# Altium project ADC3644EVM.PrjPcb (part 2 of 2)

## Sheet ADC Inputs.SchDoc: ADC Inputs
size 431 x 279 mm; Date: Not shown in title block; ApprovedBy: Not shown in title block; CheckedBy: Not shown in title block; Author: Not shown in title block; CompanyName: Not shown in title block; Engineer: Not shown in title block; Organization: Not shown in title block; Address1: Not shown in title block; Address2: Not shown in title block; Address3: Not shown in title block; Address4: Not shown in title block; DocumentNumber: 1; Revision: Use project parameter SCH_Rev; SheetNumber: 9; SheetTotal: 15; PageSetup: Record=PageOptions¦CenterHorizontal=True¦CenterVertical=True¦PrintScale=1.00¦XCorrection=1.00¦YCorrection=1.00¦PrintKind=0¦BorderSize=5000000¦LeftOffset=0¦BottomOffset=0¦Orientation=2¦PaperLength=1000¦PaperWidth=1000¦Scale=100¦PaperSource=15¦PrintQuality=600¦MediaType=1¦DitherType=10¦PaperKind=Letter¦PrintScaleMode=1

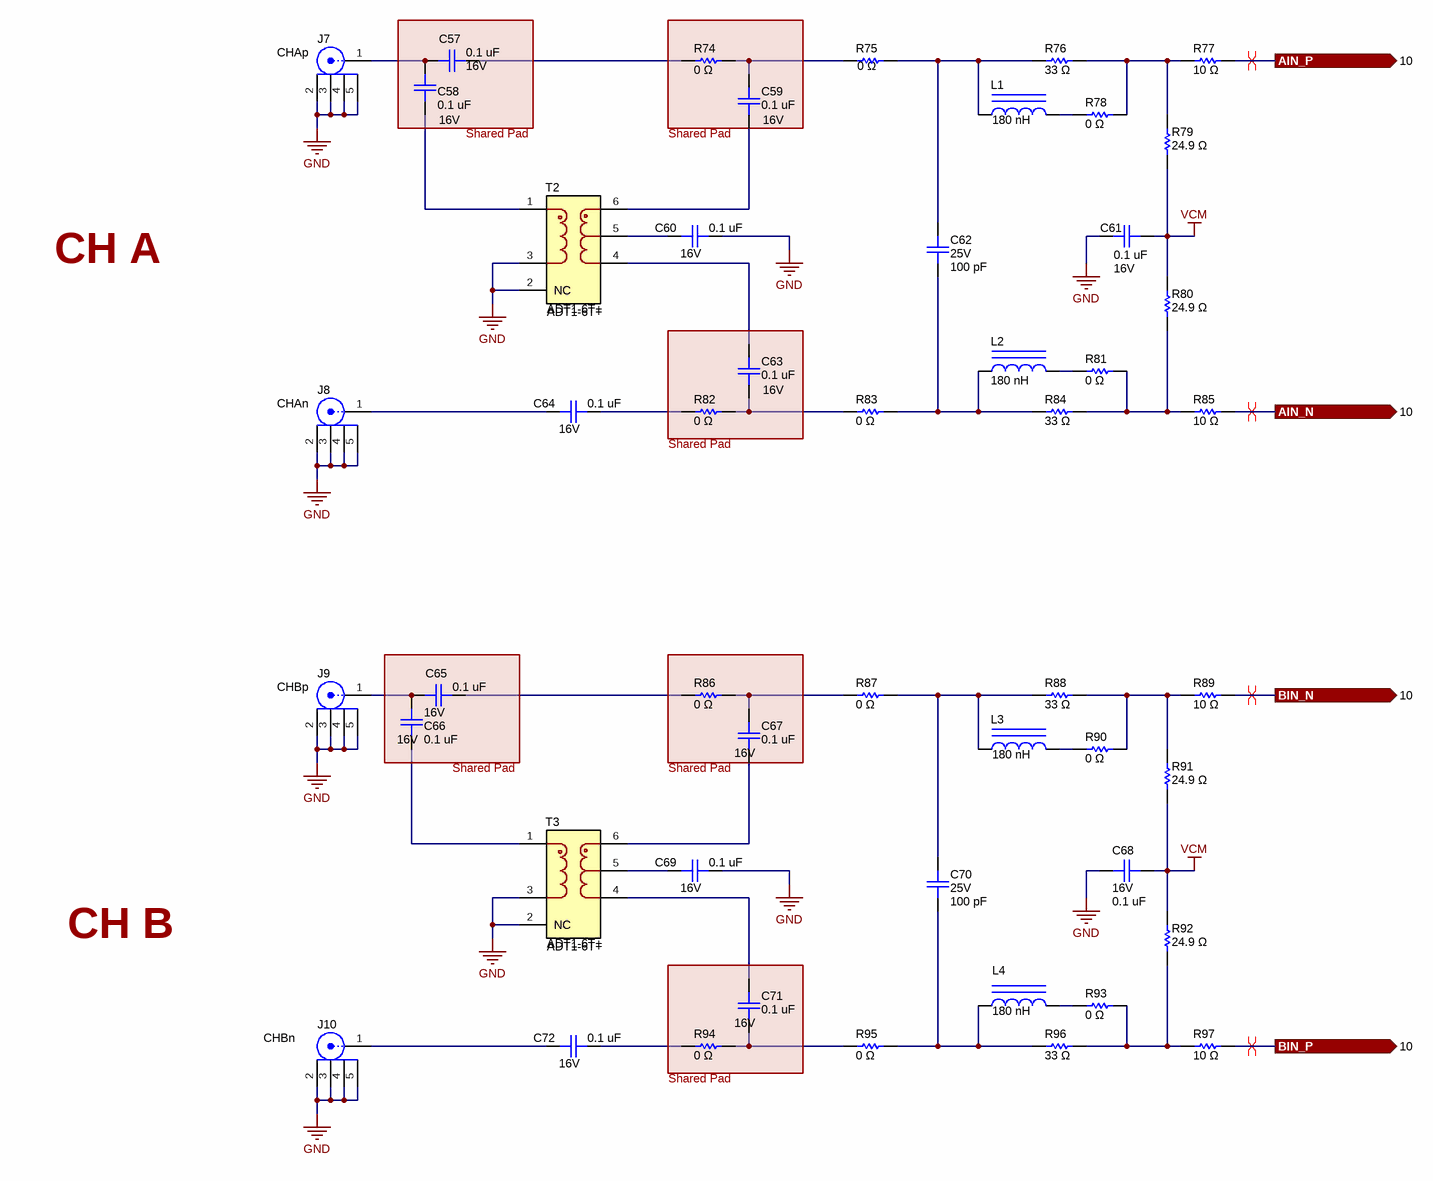
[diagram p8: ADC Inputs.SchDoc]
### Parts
(Parts that share a designator on the sheet are numbered #1, #2 ... from top to bottom, then left to right.)
?#4  Shared Pad  (graphical)
?#5  Shared Pad  (graphical)
?#6  Shared Pad  (graphical)
?#7  Shared Pad  (graphical)
?#8  Shared Pad  (graphical)
?#9  Shared Pad  (graphical)
C57  value 0.1 uF  Voltage - Rated: 16V  [0201_cap]  (hidden comment: GRM033Z71C104ME14D)
C58  value 0.1 uF  Voltage - Rated: 16V  [0201_cap]  (hidden comment: GRM033Z71C104ME14D)
C59  value 0.1 uF  Voltage - Rated: 16V  [0201_cap]  (hidden comment: GRM033Z71C104ME14D)
C60  value 0.1 uF  Voltage - Rated: 16V  [0201_cap]  (hidden comment: GRM033Z71C104ME14D)
C61  value 0.1 uF  Voltage - Rated: 16V  [0201_cap]  (hidden comment: GRM033Z71C104ME14D)
C62  value 100 pF  Voltage - Rated: 25V  [0201_cap]  (hidden comment: CGA1A2X7R1E101M030BA)
C63  value 0.1 uF  Voltage - Rated: 16V  [0201_cap]  (hidden comment: GRM033Z71C104ME14D)
C64  value 0.1 uF  Voltage - Rated: 16V  [0201_cap]  (hidden comment: GRM033Z71C104ME14D)
C65  value 0.1 uF  Voltage - Rated: 16V  [0201_cap]  (hidden comment: GRM033Z71C104ME14D)
C66  value 0.1 uF  Voltage - Rated: 16V  [0201_cap]  (hidden comment: GRM033Z71C104ME14D)
C67  value 0.1 uF  Voltage - Rated: 16V  [0201_cap]  (hidden comment: GRM033Z71C104ME14D)
C68  value 0.1 uF  Voltage - Rated: 16V  [0201_cap]  (hidden comment: GRM033Z71C104ME14D)
C69  value 0.1 uF  Voltage - Rated: 16V  [0201_cap]  (hidden comment: GRM033Z71C104ME14D)
C70  value 100 pF  Voltage - Rated: 25V  [0201_cap]  (hidden comment: CGA1A2X7R1E101M030BA)
C71  value 0.1 uF  Voltage - Rated: 16V  [0201_cap]  (hidden comment: GRM033Z71C104ME14D)
C72  value 0.1 uF  Voltage - Rated: 16V  [0201_cap]  (hidden comment: GRM033Z71C104ME14D)
J7  Text1: CHAp  [FP-132134-15_CONN_SMA_JACK-MFG]  (hidden comment: 132134-15)
J8  Text1: CHAn  [FP-132134-15_CONN_SMA_JACK-MFG]  (hidden comment: 132134-15)
J9  Text1: CHBp  [FP-132134-15_CONN_SMA_JACK-MFG]  (hidden comment: 132134-15)
J10  Text1: CHBn  [FP-132134-15_CONN_SMA_JACK-MFG]  (hidden comment: 132134-15)
L1  180 nH  [IND_LQG15H]
L2  180 nH  [IND_LQG15H]
L3  180 nH  [IND_LQG15H]
L4  180 nH  [IND_LQG15H]
R74  value 0 Ω  [0201]  (hidden comment: ERJ-1GN0R00C)
R75  value 0 Ω  [0201]  (hidden comment: ERJ-1GN0R00C)
R76  value 33 Ω  [0201]  (hidden comment: ERJ-1GNF33R0C)
R77  value 10 Ω  [0201]  (hidden comment: ERJ-1GNF10R0C)
R78  value 0 Ω  [0201]  (hidden comment: ERJ-1GN0R00C)
R79  value 24.9 Ω  [0201]  (hidden comment: ERJ-1GNF24R9C)
R80  value 24.9 Ω  [0201]  (hidden comment: ERJ-1GNF24R9C)
R81  value 0 Ω  [0201]  (hidden comment: ERJ-1GN0R00C)
R82  value 0 Ω  [0201]  (hidden comment: ERJ-1GN0R00C)
R83  value 0 Ω  [0201]  (hidden comment: ERJ-1GN0R00C)
R84  value 33 Ω  [0201]  (hidden comment: ERJ-1GNF33R0C)
R85  value 10 Ω  [0201]  (hidden comment: ERJ-1GNF10R0C)
R86  value 0 Ω  [0201]  (hidden comment: ERJ-1GN0R00C)
R87  value 0 Ω  [0201]  (hidden comment: ERJ-1GN0R00C)
R88  value 33 Ω  [0201]  (hidden comment: ERJ-1GNF33R0C)
R89  value 10 Ω  [0201]  (hidden comment: ERJ-1GNF10R0C)
R90  value 0 Ω  [0201]  (hidden comment: ERJ-1GN0R00C)
R91  value 24.9 Ω  [0201]  (hidden comment: ERJ-1GNF24R9C)
R92  value 24.9 Ω  [0201]  (hidden comment: ERJ-1GNF24R9C)
R93  value 0 Ω  [0201]  (hidden comment: ERJ-1GN0R00C)
R94  value 0 Ω  [0201]  (hidden comment: ERJ-1GN0R00C)
R95  value 0 Ω  [0201]  (hidden comment: ERJ-1GN0R00C)
R96  value 33 Ω  [0201]  (hidden comment: ERJ-1GNF33R0C)
R97  value 10 Ω  [0201]  (hidden comment: ERJ-1GNF10R0C)
T2  ADT1-6T+  [CD637]
T3  ADT1-6T+  [CD637]

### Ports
AIN_N (out, see 10), AIN_P (out, see 10), BIN_N (out, see 10), BIN_P (out, see 10)

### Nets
GND: C60.2 C61.1 C68.1 C69.2 J7.2 J7.3 J7.4 J7.5 J8.2 J8.3 J8.4 J8.5 J9.2 J9.3 J9.4 J9.5 J10.2 J10.3 J10.4 J10.5 T2.2(NC) T2.3 T3.2(NC) T3.3
VCM: C61.2 C68.2 R79.1 R80.2 R91.1 R92.2
AIN_N: R85.2 ; port AIN_N
AIN_P: R77.2 ; port AIN_P
BIN_N: R89.2 ; port BIN_N
BIN_P: R97.2 ; port BIN_P
NetC57_1: C57.1 C58.1 J7.1
NetC57_2: C57.2 R74.1
NetC58_2: C58.2 T2.1
NetC59_1: C59.1 T2.6
NetC59_2: C59.2 R74.2 R75.1
NetC60_1: C60.1 T2.5
NetC62_1: C62.1 L2.1 R83.2 R84.1
NetC62_2: C62.2 L1.1 R75.2 R76.1
NetC63_1: C63.1 R82.2 R83.1
NetC63_2: C63.2 T2.4
NetC64_1: C64.1 J8.1
NetC64_2: C64.2 R82.1
NetC65_1: C65.1 C66.1 J9.1
NetC65_2: C65.2 R86.1
NetC66_2: C66.2 T3.1
NetC67_1: C67.1 T3.6
NetC67_2: C67.2 R86.2 R87.1
NetC69_1: C69.1 T3.5
NetC70_1: C70.1 L4.1 R95.2 R96.1
NetC70_2: C70.2 L3.1 R87.2 R88.1
NetC71_1: C71.1 R94.2 R95.1
NetC71_2: C71.2 T3.4
NetC72_1: C72.1 J10.1
NetC72_2: C72.2 R94.1
NetL1_2: L1.2 R78.1
NetL2_2: L2.2 R81.1
NetL3_2: L3.2 R90.1
NetL4_2: L4.2 R93.1
NetR76_2: R76.2 R77.1 R78.2 R79.2
NetR80_1: R80.1 R81.2 R84.2 R85.1
NetR88_2: R88.2 R89.1 R90.2 R91.2
NetR92_1: R92.1 R93.2 R96.2 R97.1

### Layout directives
differential pair: AIN_N, AIN_P, BIN_N, BIN_P

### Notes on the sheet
- CH A
- CH B

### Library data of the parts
?#4-?#9 = Swizzle: Schematic notation to show that the pads of two components should be overlapped
C57-C61 C63-C69 C71 C72 = capcc09270: CAP CER 0.1UF 16V X7R 0201; Manufacturer: Murata Electronics; CompType: Capacitor Ceramic; Tolerance: ±20%; SizeX_mm: 0.6; SizeY_mm: 0.3; SizeZ_mm: 0.33
C62 C70 = capcc06388: CAP CER 100PF 25V X7R 0201; Manufacturer: TDK Corporation; CompType: Capacitor Ceramic; Tolerance: ±20%; SizeX_mm: 0.6; SizeY_mm: 0.3; SizeZ_mm: 0.33
J7-J10 = 132134-15: SMA Connector Jack, Female Socket 50Ohm Surface Mount, Through Hole Solder; Manufacturer: Amphenol RF; UniqueID: cmp00028; CompType: RF Connector
L1-L4 = LQG15HSR18J02D: Inductor, Multilayer, Air Core, 180 nH, 0.14 A, 3.38 ohm, SMD; Manufacturer: MuRata; Isat: 0.14A @ % inductance drop; Irms: 0.14A @ C rise; Green_Lifecycle: Active; SizeAreaWB_mm2: 3; DCR_ohm: 3.38; Green_REACh: Passed; Value: 180nH; Imax_A: 140mA; SizeZ_mm: 0.55; SizeX_mm: 1; SizeY_mm: 0.5; Value2: 0.14A; AEC Category: Q200
R74 R75 R78 R81-R83 R86 R87 R90 R93-R95 = RSMD020101699: RES SMD 0 OHM JUMPER 1/20W 0201; Manufacturer: Panasonic Electronic Components; CompType: Resistor SMD; Power (Watts): 0.05W, 1/20W
R76 R84 R88 R96 = RSMD020100013: RES SMD 33 OHM 1% 1/20W 0201; Manufacturer: Panasonic Electronic Components; CompType: Resistor SMD; Power (Watts): 0.05W, 1/20W; Temperature Coefficient: ±200ppm/°C
R77 R85 R89 R97 = RSMD020100179: RES SMD 10 OHM 1% 1/20W 0201; Manufacturer: Panasonic Electronic Components; CompType: Resistor SMD; Power (Watts): 0.05W, 1/20W; Temperature Coefficient: ±200ppm/°C
R79 R80 R91 R92 = RSMD020100010: RES SMD 24.9 OHM 1% 1/20W 0201; Manufacturer: Panasonic Electronic Components; CompType: Resistor SMD; Power (Watts): 0.05W, 1/20W; Temperature Coefficient: ±200ppm/°C
T2 T3 = ADT1-6T+: Transformer 50Ω/0.03 to 125 MHz; Manufacturer: Mini-Circuits; Rsec1_ohm: 50; Symbol Name: SYM-ADT1-6T+; Ns1toNp: 1:1; SizeZ_mm: .206inch; AEC Qualified: No

## Sheet DUT IO.SchDoc: ADC IO
size 431 x 279 mm; Date: Not shown in title block; ApprovedBy: Not shown in title block; CheckedBy: Not shown in title block; Author: Not shown in title block; CompanyName: Not shown in title block; Engineer: Not shown in title block; Organization: Not shown in title block; Address1: Not shown in title block; Address2: Not shown in title block; Address3: Not shown in title block; Address4: Not shown in title block; DocumentNumber: 1; Revision: Use project parameter SCH_Rev; SheetNumber: 10; SheetTotal: 15; PageSetup: Record=PageOptions¦CenterHorizontal=True¦CenterVertical=True¦PrintScale=1.00¦XCorrection=1.00¦YCorrection=1.00¦PrintKind=0¦BorderSize=5000000¦LeftOffset=0¦BottomOffset=0¦Orientation=2¦PaperLength=1000¦PaperWidth=1000¦Scale=100¦PaperSource=15¦PrintQuality=600¦MediaType=1¦DitherType=10¦PaperKind=Letter¦PrintScaleMode=1

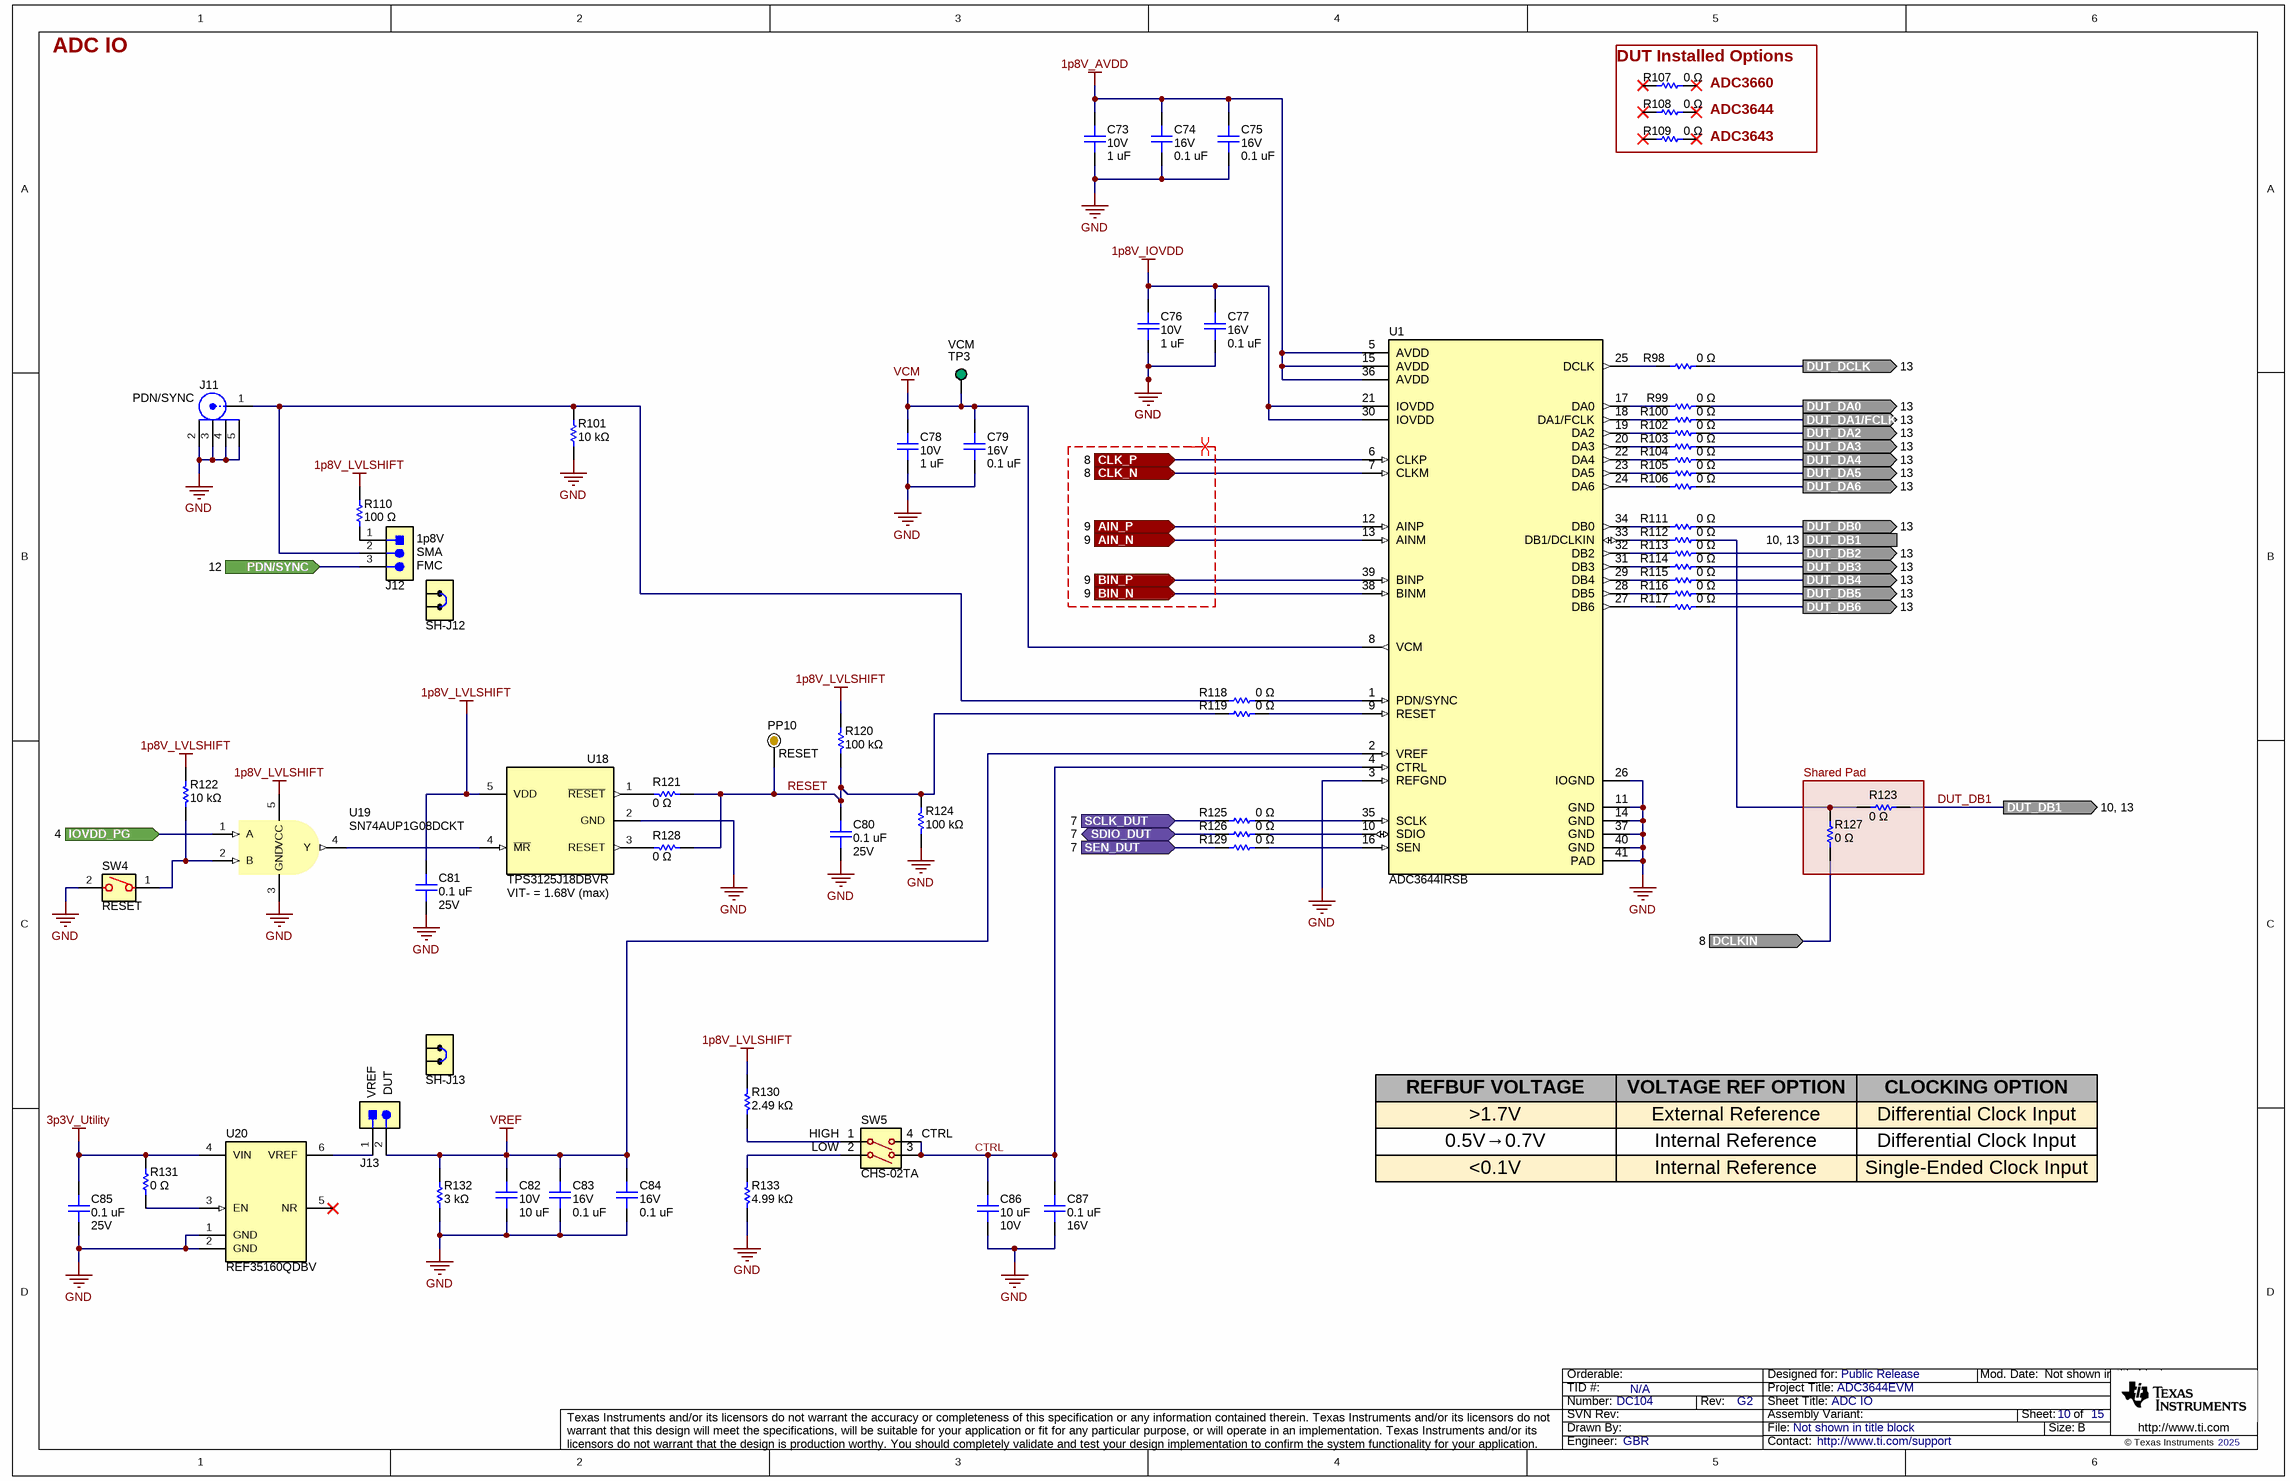
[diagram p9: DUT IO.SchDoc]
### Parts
(Parts that share a designator on the sheet are numbered #1, #2 ... from top to bottom, then left to right.)
?#10  Shared Pad  (graphical)
C73  value 1 uF  Voltage - Rated: 10V  [0201_cap]  (hidden comment: GRM033R61A105ME44D)
C74  value 0.1 uF  Voltage - Rated: 16V  [0201_cap]  (hidden comment: GRM033Z71C104ME14D)
C75  value 0.1 uF  Voltage - Rated: 16V  [0201_cap]  (hidden comment: GRM033Z71C104ME14D)
C76  value 1 uF  Voltage - Rated: 10V  [0201_cap]  (hidden comment: GRM033R61A105ME44D)
C77  value 0.1 uF  Voltage - Rated: 16V  [0201_cap]  (hidden comment: GRM033Z71C104ME14D)
C78  value 1 uF  Voltage - Rated: 10V  [0201_cap]  (hidden comment: GRM033R61A105ME44D)
C79  value 0.1 uF  Voltage - Rated: 16V  [0201_cap]  (hidden comment: GRM033Z71C104ME14D)
C80  value 0.1 uF  Voltage - Rated: 25V  [0402L_cap]  (hidden comment: GRT155R71E104KE01J)
C81  value 0.1 uF  Voltage - Rated: 25V  [0402L_cap]  (hidden comment: GRT155R71E104KE01J)
C82  value 10 uF  Voltage - Rated: 10V  [0402L_cap]  (hidden comment: 0402ZD106MAT2A)
C83  value 0.1 uF  Voltage - Rated: 16V  [0201_cap]  (hidden comment: GRM033Z71C104ME14D)
C84  value 0.1 uF  Voltage - Rated: 16V  [0201_cap]  (hidden comment: GRM033Z71C104ME14D)
C85  value 0.1 uF  Voltage - Rated: 25V  [0402L_cap]  (hidden comment: GRT155R71E104KE01J)
C86  value 10 uF  Voltage - Rated: 10V  [0402L_cap]  (hidden comment: 0402ZD106MAT2A)
C87  value 0.1 uF  Voltage - Rated: 16V  [0201_cap]  (hidden comment: GRM033Z71C104ME14D)
J11  Text1: PDN/SYNC  [FP-132134-15_CONN_SMA_JACK-MFG]  (hidden comment: 132134-15)
J12  Text3: FMC  Text2: SMA  Text1: 1p8V  [PBC03SAAN]  (hidden comment: TSW-103-14-L-S)
J13  Text2: DUT  Text1: VREF  [HDR_2x1_TH_VT_50mil]  (hidden comment: GRPB021VWVN-RC)
PP10  Text1: RESET  [ProbePoint_TH_40mil]  (hidden comment: Probe Point)  (no BOM)
R98  value 0 Ω  [0201]  (hidden comment: ERJ-1GN0R00C)
R99  value 0 Ω  [0201]  (hidden comment: ERJ-1GN0R00C)
R100  value 0 Ω  [0201]  (hidden comment: ERJ-1GN0R00C)
R101  value 10 kΩ  [0402L]  (hidden comment: ERA-2AEB103X)
R102  value 0 Ω  [0201]  (hidden comment: ERJ-1GN0R00C)
R103  value 0 Ω  [0201]  (hidden comment: ERJ-1GN0R00C)
R104  value 0 Ω  [0201]  (hidden comment: ERJ-1GN0R00C)
R105  value 0 Ω  [0201]  (hidden comment: ERJ-1GN0R00C)
R106  value 0 Ω  [0201]  (hidden comment: ERJ-1GN0R00C)
R107  value 0 Ω  [0805L]  (hidden comment: ERJ-6GEY0R00V)
R108  value 0 Ω  [0805L]  (hidden comment: ERJ-6GEY0R00V)
R109  value 0 Ω  [0805L]  (hidden comment: ERJ-6GEY0R00V)
R110  value 100 Ω  [0402L]  (hidden comment: ERJ-2GEJ101X)
R111  value 0 Ω  [0201]  (hidden comment: ERJ-1GN0R00C)
R112  value 0 Ω  [0201]  (hidden comment: ERJ-1GN0R00C)
R113  value 0 Ω  [0201]  (hidden comment: ERJ-1GN0R00C)
R114  value 0 Ω  [0201]  (hidden comment: ERJ-1GN0R00C)
R115  value 0 Ω  [0201]  (hidden comment: ERJ-1GN0R00C)
R116  value 0 Ω  [0201]  (hidden comment: ERJ-1GN0R00C)
R117  value 0 Ω  [0201]  (hidden comment: ERJ-1GN0R00C)
R118  value 0 Ω  [0201]  (hidden comment: ERJ-1GN0R00C)
R119  value 0 Ω  [0201]  (hidden comment: ERJ-1GN0R00C)
R120  value 100 kΩ  [0402L]  (hidden comment: ERJ-2GEJ104X)
R121  value 0 Ω  [0402L]  (hidden comment: ERJ-U020R00X)
R122  value 10 kΩ  [0402L]  (hidden comment: ERA-2AEB103X)
R123  value 0 Ω  [0201]  (hidden comment: ERJ-1GN0R00C)
R124  value 100 kΩ  [0402L]  (hidden comment: ERJ-2GEJ104X)
R125  value 0 Ω  [0201]  (hidden comment: ERJ-1GN0R00C)
R126  value 0 Ω  [0201]  (hidden comment: ERJ-1GN0R00C)
R127  value 0 Ω  [0201]  (hidden comment: ERJ-1GN0R00C)
R128  value 0 Ω  [0402L]  (hidden comment: ERJ-U020R00X)
R129  value 0 Ω  [0201]  (hidden comment: ERJ-1GN0R00C)
R130  value 2.49 kΩ  [0201]  (hidden comment: ERJ-1GNF2491C)
R131  value 0 Ω  [0201]  (hidden comment: ERJ-1GN0R00C)
R132  value 3 kΩ  [0201]  (hidden comment: ERJ-1GNF3001C)
R133  value 4.99 kΩ  [0201]  (hidden comment: ERJ-1GNF4991C)
SH-J12  SPC02SYAN  [SPC02SYAN]  (value not drawn)
SH-J13  HMSC-G  [HMSC-G]  (value not drawn)
SW4  Text1: RESET  [FSMSM]  (hidden comment: FSMSM)
SW5  CHS-02TA  Text4: CTRL  Text2: LOW  Text1: HIGH  [CHS-02TA]
TP3  Text1: VCM  [KEYSTONE5116]  (hidden comment: 5116)
U1  ADC3644IRSB  [RSB0040E]
U18  TPS3125J18DBVR  Text1: VIT- = 1.68V (max)  [DBV0005A]
U19  SN74AUP1G08DCKT  [DCK0005A]
U20  REF35160QDBV  [DBV0006A]

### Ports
AIN_N (in, see 9), AIN_P (in, see 9), BIN_N (in, see 9), BIN_P (in, see 9), CLK_N (in, see 8), CLK_P (in, see 8), DCLKIN (in, see 8), DUT_DA0 (out, see 13), DUT_DA1/FCLK (out, see 13), DUT_DA2 (out, see 13), DUT_DA3 (out, see 13), DUT_DA4 (out, see 13), DUT_DA5 (out, see 13), DUT_DA6 (out, see 13), DUT_DB0 (out, see 13), DUT_DB1 (out, see 10, 13), DUT_DB2 (out, see 13), DUT_DB3 (out, see 13), DUT_DB4 (out, see 13), DUT_DB5 (out, see 13), DUT_DB6 (out, see 13), DUT_DCLK (out, see 13), IOVDD_PG (in, see 4), PDN/SYNC (in, see 12), SCLK_DUT (in, see 7), SDIO_DUT (bidir, see 7), SEN_DUT (in, see 7)

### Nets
1p8V_AVDD: C73.2 C74.2 C75.2 U1.5(AVDD) U1.15(AVDD) U1.36(AVDD)
1p8V_IOVDD: C76.2 C77.2 U1.21(IOVDD) U1.30(IOVDD)
1p8V_LVLSHIFT: C81.2 R110.2 R120.2 R122.1 R130.2 U18.5(VDD) U19.5(VCC)
3p3V_Utility: C85.2 R131.2 U20.4(VIN)
GND: C73.1 C74.1 C75.1 C76.1 C77.1 C78.1 C79.1 C80.1 C81.1 C82.1 C83.1 C84.1 C85.1 C86.1 C87.1 J11.2 J11.3 J11.4 J11.5 R101.1 R124.1 R132.1 R133.1 SW4.2 U1.3(REFGND) U1.11(GND) U1.14(GND) U1.26(IOGND) U1.37(GND) U1.40(GND) U1.41(PAD) U18.2(GND) U19.3(GND) U20.1(GND) U20.2(GND)
VCM: C78.2 C79.2 TP3.1 U1.8(VCM)
VREF: C82.2 C83.2 C84.2 J13.2 R132.2 U1.2(VREF)
AIN_N: U1.13(AINM) ; port AIN_N
AIN_P: U1.12(AINP) ; port AIN_P
BIN_N: U1.38(BINM) ; port BIN_N
BIN_P: U1.39(BINP) ; port BIN_P
CLK_N: U1.7(CLKM) ; port CLK_N
CLK_P: U1.6(CLKP) ; port CLK_P
CTRL: C86.2 C87.2 SW5.3(OFF) SW5.4(OFF) U1.4(CTRL)
DCLKIN: R127.1 ; port DCLKIN
DUT_DA0: R99.2 ; port DUT_DA0
DUT_DA1/FCLK: R100.2 ; port DUT_DA1/FCLK
DUT_DA2: R102.2 ; port DUT_DA2
DUT_DA3: R103.2 ; port DUT_DA3
DUT_DA4: R104.2 ; port DUT_DA4
DUT_DA5: R105.2 ; port DUT_DA5
DUT_DA6: R106.2 ; port DUT_DA6
DUT_DB0: R111.2 ; port DUT_DB0
DUT_DB1: R123.1 ; port DUT_DB1
DUT_DB2: R113.2 ; port DUT_DB2
DUT_DB3: R114.2 ; port DUT_DB3
DUT_DB4: R115.2 ; port DUT_DB4
DUT_DB5: R116.2 ; port DUT_DB5
DUT_DB6: R117.2 ; port DUT_DB6
DUT_DCLK: R98.2 ; port DUT_DCLK
IOVDD_PG: U19.1(A) ; port IOVDD_PG
PDN/SYNC: J12.3 ; port PDN/SYNC
RESET: C80.2 PP10.1 R119.1 R120.1 R121.1 R124.2 R128.1
SCLK_DUT: R125.1 ; port SCLK_DUT
SDIO_DUT: R126.1 ; port SDIO_DUT
SEN_DUT: R129.1 ; port SEN_DUT
NetJ11_1: J11.1 J12.2 R101.2 R118.1
NetJ12_1: J12.1 R110.1
NetJ13_1: J13.1 U20.6(VREF)
NetR98_1: R98.1 U1.25(DCLK)
NetR99_1: R99.1 U1.17(DA0)
NetR100_1: R100.1 U1.18(DA1/FCLK)
NetR102_1: R102.1 U1.19(DA2)
NetR103_1: R103.1 U1.20(DA3)
NetR104_1: R104.1 U1.22(DA4)
NetR105_1: R105.1 U1.23(DA5)
NetR106_1: R106.1 U1.24(DA6)
NetR111_1: R111.1 U1.34(DB0)
NetR112_1: R112.1 U1.33(DB1/DCLKIN)
NetR112_2: R112.2 R123.2 R127.2
NetR113_1: R113.1 U1.32(DB2)
NetR114_1: R114.1 U1.31(DB3)
NetR115_1: R115.1 U1.29(DB4)
NetR116_1: R116.1 U1.28(DB5)
NetR117_1: R117.1 U1.27(DB6)
NetR118_2: R118.2 U1.1(PDN/SYNC)
NetR119_2: R119.2 U1.9(RESET)
NetR121_2: R121.2 U18.1(~{RESET})
NetR122_2: R122.2 SW4.1 U19.2(B)
NetR125_2: R125.2 U1.35(SCLK)
NetR126_2: R126.2 U1.10(SDIO)
NetR128_2: R128.2 U18.3(RESET)
NetR129_2: R129.2 U1.16(SEN)
NetR130_1: R130.1 SW5.1(ON)
NetR131_1: R131.1 U20.3(EN)
NetR133_2: R133.2 SW5.2(ON)
NetU18_4: U18.4(~{MR}) U19.4(Y)

Not connected (* = marked no-connect by the designer): R107 1* 2*; R108 1* 2*; R109 1* 2*; U20 5(NR)*

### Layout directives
differential pair; net class DiffPairIN: (no net found under the mark)

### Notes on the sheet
- ADC3660
- DUT Installed Options
- ADC3644
- ADC3643
- REFBUF VOLTAGE
- VOLTAGE REF OPTION
- CLOCKING OPTION
- >1.7V
- 0.5V→0.7V
- External Reference
- Internal Reference
- Differential Clock Input
- <0.1V
- Single-Ended Clock Input

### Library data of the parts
?#10 = Swizzle: as ?#4-?#9 on sheet ADC Inputs
C73 C76 C78 = capcc09264: CAP CER 1UF 10V X5R 0201; Manufacturer: Murata Electronics; CompType: Capacitor Ceramic; Tolerance: ±20%; SizeX_mm: 0.6; SizeY_mm: 0.3; SizeZ_mm: 0.33
C74 C75 C77 C79 C83 C84 C87 = capcc09270: as C57-C61 on sheet ADC Inputs
C80 C81 C85 = capcc09401: CAP CER 0.1UF 25V X7R 0402; Manufacturer: Murata; CompType: Capacitor Ceramic; Tolerance: ±10%; SizeX_mm: 1; SizeY_mm: 0.5; SizeZ_mm: 0.7
C82 C86 = capcc09406: CAP CER 10UF 10V X5R 0402; Manufacturer: KYOCERA AVX; CompType: Capacitor Ceramic; Tolerance: ±20%; SizeX_mm: 1; SizeY_mm: 0.5; SizeZ_mm: 0.7
J11 = 132134-15: as J7-J10 on sheet ADC Inputs
J12 = TSW-103-14-L-S: Header, 100mil, 3x1, Gold, TH; Manufacturer: Samtec; Alt Manufacturer: Sullins Connector Solutions; UniqueID: cmp00015; Pitch (mm): 2.54
J13 = cmp00298: Header, 50mil, 2x1, Gold, TH; Manufacturer: Sullins Connector Solutions; Pitch (mm): 1.27
PP10 = Probe Point: Probe Point that can be used in lue of a test point; UniqueID: cmp00025
R98-R100 R102-R106 R111-R119 R123 R125-R127 R129 R131 = RSMD020101699: as R74 on sheet ADC Inputs
R101 R122 = RSMD040200315: RES SMD 10K OHM 0.1% 1/16W 0402; Manufacturer: Panasonic Electronic Components; CompType: Resistor SMD; Power (Watts): 0.063W, 1/16W; Temperature Coefficient: ±25ppm/°C; SizeX_mm: 1; SizeY_mm: 0.5; SizeZ_mm: 0.4
R107-R109 = RSMD080510615: RES SMD 0 OHM JUMPER 1/8W 0805; Manufacturer: Panasonic Electronic Components; CompType: Resistor SMD; Power (Watts): 0.125W, 1/8W; SizeX_mm: 2; SizeY_mm: 1.25; SizeZ_mm: 0.7
R110 = RSMD040200370: RES SMD 100 OHM 5% 1/10W 0402; Manufacturer: Panasonic Electronic Components; CompType: Resistor SMD; Power (Watts): 0.1W, 1/10W; Temperature Coefficient: ±200ppm/°C; SizeX_mm: 1; SizeY_mm: 0.5; SizeZ_mm: 0.4
R120 R124 = RSMD040200354: RES SMD 100K OHM 5% 1/10W 0402; Manufacturer: Panasonic Electronic Components; CompType: Resistor SMD; Power (Watts): 0.1W, 1/10W; Temperature Coefficient: ±200ppm/°C; SizeX_mm: 1; SizeY_mm: 0.5; SizeZ_mm: 0.4
R121 R128 = RSMD040200004: RES 0 OHM JUMPER 0402 SMD; Manufacturer: Panasonic Electronic Components; CompType: Resistor SMD; Power (Watts): 0.1W, 1/10W; Temperature Coefficient: -100/ +600ppm/°C; SizeX_mm: 1; SizeY_mm: 0.5; SizeZ_mm: 0.4
R130 = RSMD020100692: RES SMD 2.49K OHM 1% 1/20W 0201; Manufacturer: Panasonic Electronic Components; CompType: Resistor SMD; Power (Watts): 0.05W, 1/20W; Temperature Coefficient: ±200ppm/°C
R132 = RSMD020100769: RES SMD 3K OHM 1% 1/20W 0201; Manufacturer: Panasonic Electronic Components; CompType: Resistor SMD; Power (Watts): 0.05W, 1/20W; Temperature Coefficient: ±200ppm/°C
R133 = RSMD020100641: RES SMD 4.99K OHM 1% 1/20W 0201; Manufacturer: Panasonic Electronic Components; CompType: Resistor SMD; Power (Watts): 0.05W, 1/20W; Temperature Coefficient: ±200ppm/°C
SH-J12 = cmp00299: 2 (1 x 2) Position Shunt Connector Black Closed Top 0.050" (1.27mm) Gold; Manufacturer: Adam Tech; PartNumber: HMSC-G; Value: 1x2; Note: You can "mate" this to a header by matching the designator.  i.e. use SH-J3 for header J3; Pitch (mm): 1.27
SH-J13 = HMSC-G: 2 (1 x 2) Position Shunt Connector Black Closed Top 0.050" (1.27mm) Gold; Manufacturer: Adam Tech; Value: 1x2; Key: SPC02SYAN; Note: You can "mate" this to a header by matching the designator.  i.e. use SH-J3 for header J3; Pitch (mm): 1.27
SW4 = cmp00234: SWITCH TACTILE SPST-NO 0.05A 24V; Manufacturer: TE Connectivity; CompType: Push Button
SW5 = CHS-02TA: SWITCH SLIDE DIP SPST 0.1A 6V; Manufacturer: Nidec Components Corporation; CompType: Swtich
TP3 = cmp00057: Test Point, Miniature, Green, TH; Manufacturer: Keystone
U1 = ADC3644IRSB: 14-Bit, 125-MSPS, Low-Noise, Ultra-Low Power Dual Channel ADC, RSB0040B (WQFN-40); Manufacturer: Texas Instruments; Alternate PartNumber: ADC3644IRSBR; PartNumber: ADC3644IRSBT
U18 = cmp00229: Push-pull, supply voltage supervisor with manual reset; Manufacturer: Texas Instruments; Alt PartNumber: TPS3125J18DBVT; CompType: Voltage Detector
U19 = cmp00268: SN74AUP1G08 Low-Power Single 2-Input Positive-AND Gate; Manufacturer: Texas Instruments
U20 = cmp00301: Ultra Low-Power, High-Precision Voltage Reference; Manufacturer: Texas Instruments; Pitch (mm): 1.27

## Sheet FMC+ Sections A-E.SchDoc: FMC+ Section Rows A - E
size 431 x 279 mm; Date: Not shown in title block; ApprovedBy: Not shown in title block; CheckedBy: Not shown in title block; Author: Not shown in title block; CompanyName: Not shown in title block; Engineer: Not shown in title block; Organization: Not shown in title block; Address1: Not shown in title block; Address2: Not shown in title block; Address3: Not shown in title block; Address4: Not shown in title block; DocumentNumber: 2; Revision: Use project parameter SCH_Rev; SheetNumber: 11; SheetTotal: 15; PageSetup: Record=PageOptions¦CenterHorizontal=True¦CenterVertical=True¦PrintScale=1.00¦XCorrection=1.00¦YCorrection=1.00¦PrintKind=0¦BorderSize=5000000¦LeftOffset=0¦BottomOffset=0¦Orientation=2¦PaperLength=1000¦PaperWidth=1000¦Scale=100¦PaperSource=15¦PrintQuality=600¦MediaType=1¦DitherType=10¦PaperKind=Letter¦PrintScaleMode=1

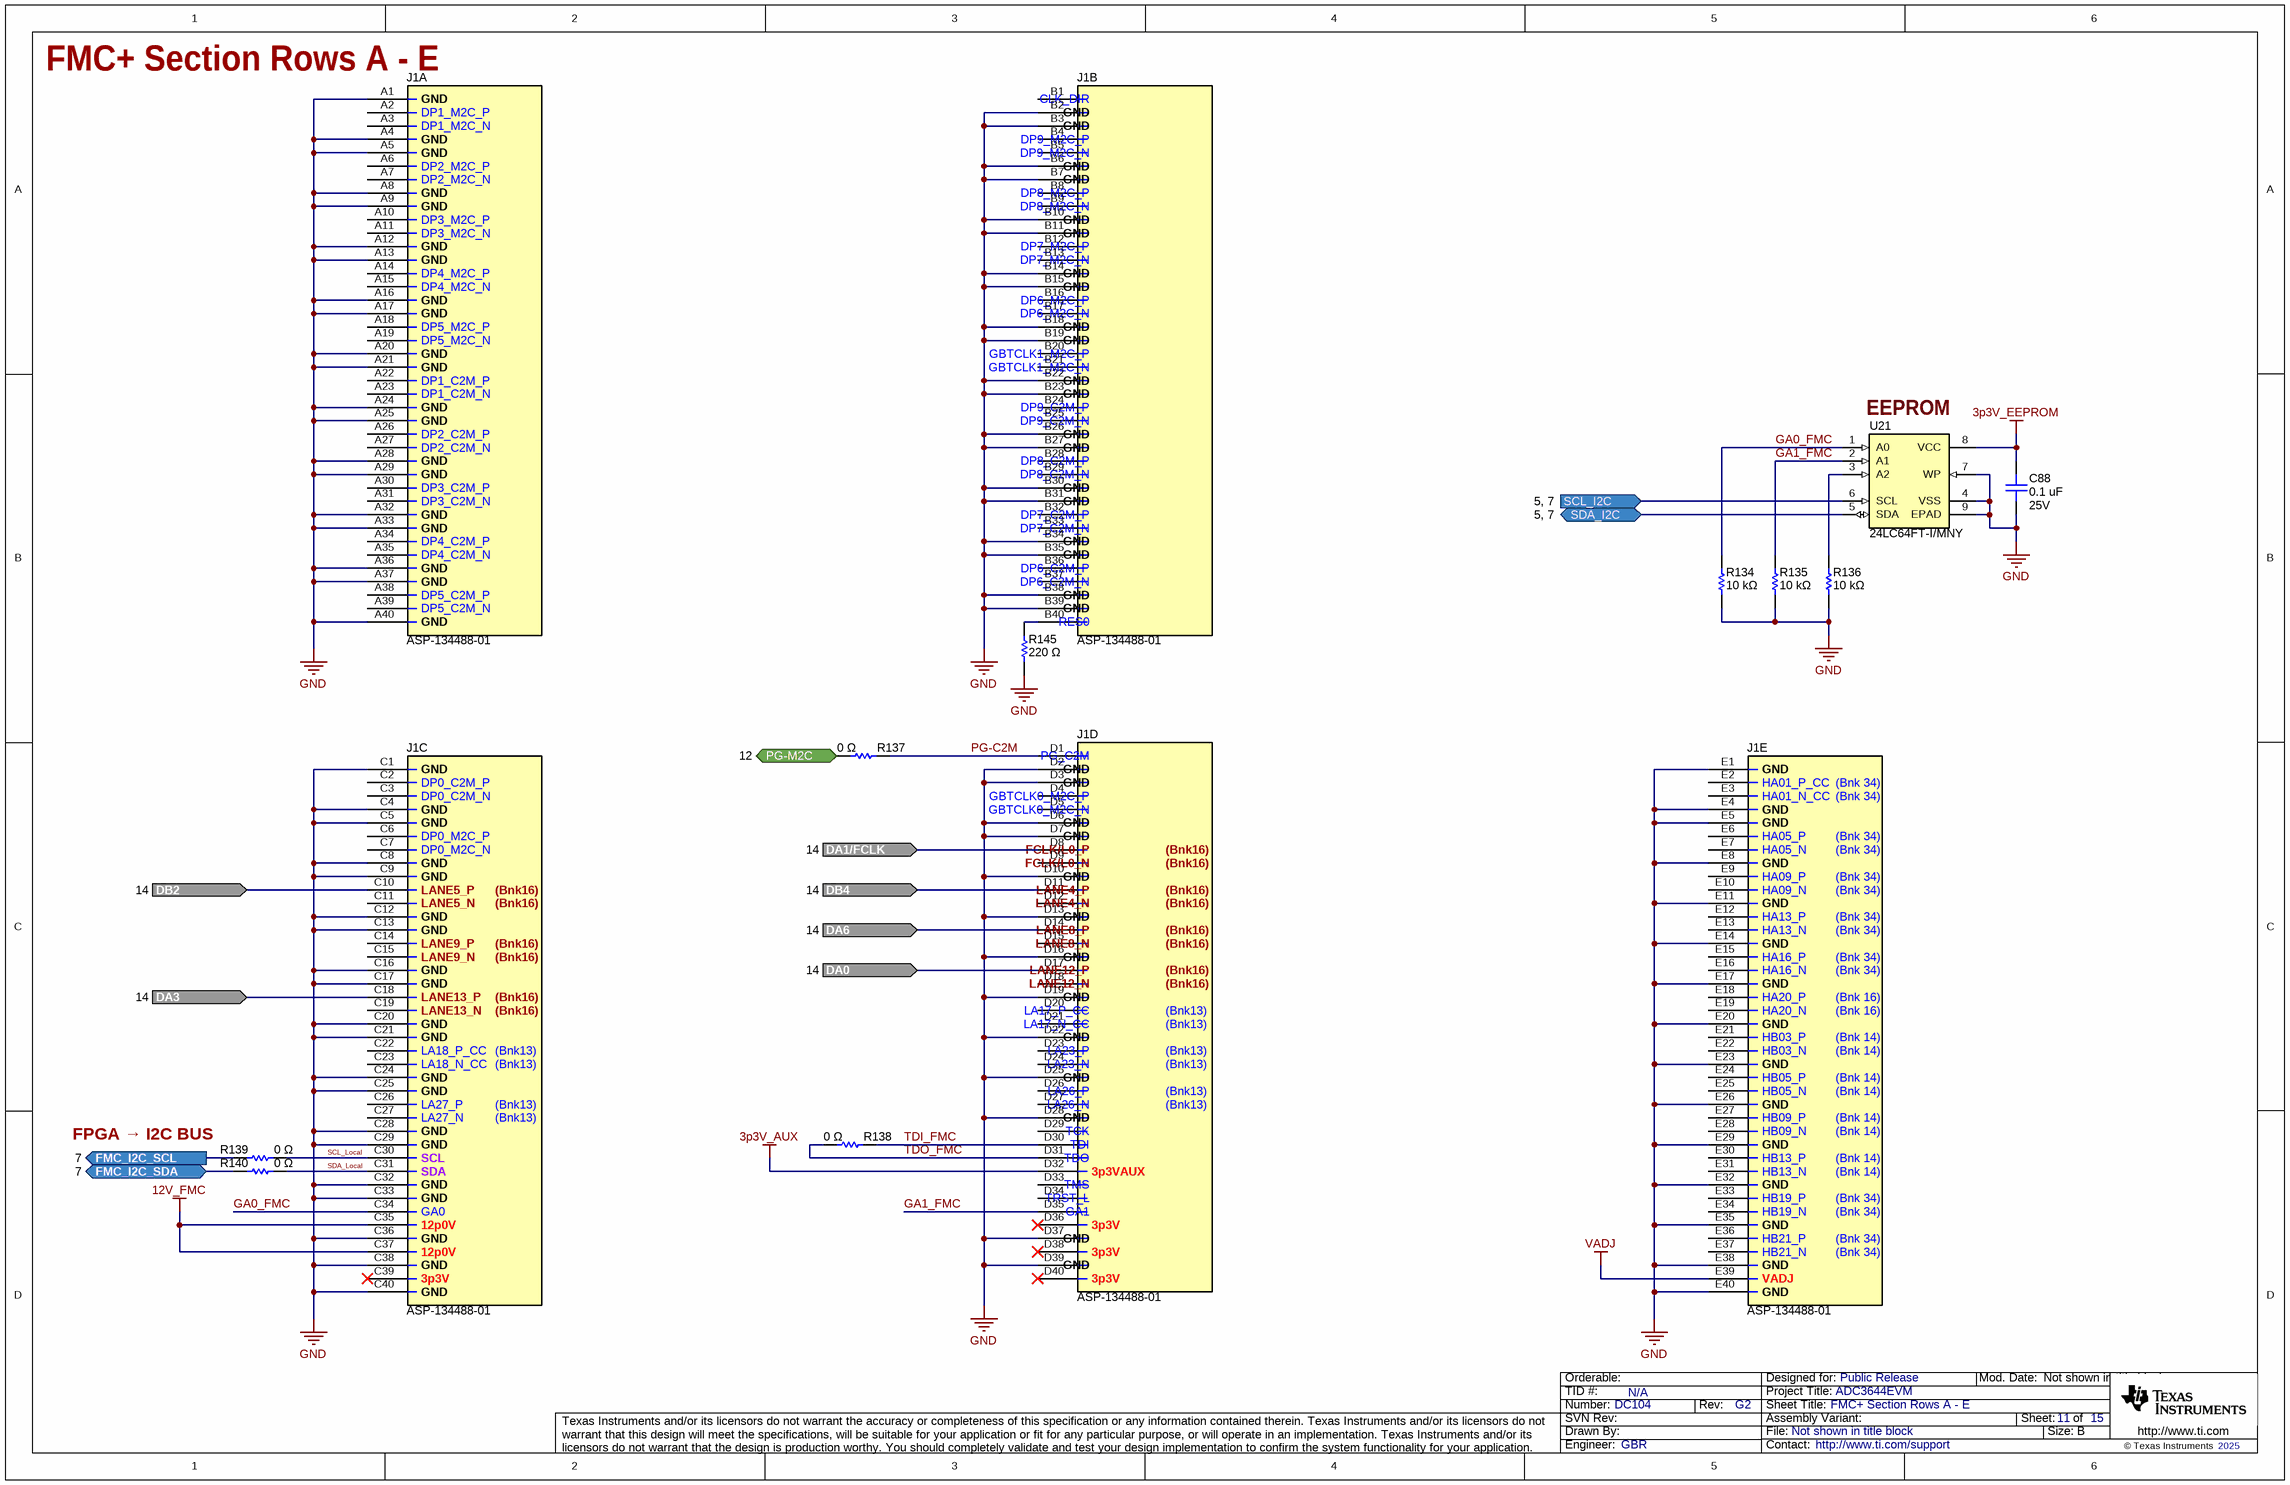
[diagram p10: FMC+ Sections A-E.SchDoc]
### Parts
C88  value 0.1 uF  Voltage - Rated: 25V  [0402L_cap]  (hidden comment: GRT155R71E104KE01J)
J1  ASP-134488-01  [SAMTEC_ASP-134488-01]  (parts A,B,C,D,E of 10)
R134  value 10 kΩ  [0201]  (hidden comment: ERJ-1GNJ103C)
R135  value 10 kΩ  [0201]  (hidden comment: ERJ-1GNJ103C)
R136  value 10 kΩ  [0201]  (hidden comment: ERJ-1GNJ103C)
R137  value 0 Ω  [0201]  (hidden comment: ERJ-1GN0R00C)
R138  value 0 Ω  [0201]  (hidden comment: ERJ-1GN0R00C)
R139  value 0 Ω  [0201]  (hidden comment: ERJ-1GN0R00C)
R140  value 0 Ω  [0201]  (hidden comment: ERJ-1GN0R00C)
R145  value 220 Ω  [0201]  (hidden comment: ERJ-1GNF2200C)
U21  24LC64FT-I/MNY  [TDFN8]

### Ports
DA0 (in, see 14), DA1/FCLK (in, see 14), DA3 (in, see 14), DA6 (in, see 14), DB2 (in, see 14), DB4 (in, see 14), FMC_I2C_SCL (out, see 7), FMC_I2C_SDA (bidir, see 7), PG-M2C (bidir, see 12), SCL_I2C (in, see 5, 7), SDA_I2C (bidir, see 5, 7)

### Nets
3p3V_AUX: J1.D32
3p3V_EEPROM: C88.2 U21.8(VCC)
12V_FMC: J1.C35 J1.C37
GND: C88.1 J1.A1 J1.A4 J1.A5 J1.A8 J1.A9 J1.A12 J1.A13 J1.A16 J1.A17 J1.A20 J1.A21 J1.A24 J1.A25 J1.A28 J1.A29 J1.A32 J1.A33 J1.A36 J1.A37 J1.A40 J1.B2 J1.B3 J1.B6 J1.B7 J1.B10 J1.B11 J1.B14 J1.B15 J1.B18 J1.B19 J1.B22 J1.B23 J1.B26 J1.B27 J1.B30 J1.B31 J1.B34 J1.B35 J1.B38 J1.B39 J1.C1 J1.C4 J1.C5 J1.C8 J1.C9 J1.C12 J1.C13 J1.C16 J1.C17 J1.C20 J1.C21 J1.C24 J1.C25 J1.C28 J1.C29 J1.C32 J1.C33 J1.C36 J1.C38 J1.C40 J1.D2 J1.D3 J1.D6 J1.D7 J1.D10 J1.D13 J1.D16 J1.D19 J1.D22 J1.D25 J1.D28 J1.D37 J1.D39 J1.E1 J1.E4 J1.E5 J1.E8 J1.E11 J1.E14 J1.E17 J1.E20 J1.E23 J1.E26 J1.E29 J1.E32 J1.E35 J1.E38 J1.E40 R134.1 R135.1 R136.1 R145.1 U21.4(VSS) U21.7(WP) U21.9(EPAD)
VADJ: J1.E39
DA0: J1.D17 ; port DA0
DA1/FCLK: J1.D8 ; port DA1/FCLK
DA3: J1.C18 ; port DA3
DA6: J1.D14 ; port DA6
DB2: J1.C10 ; port DB2
DB4: J1.D11 ; port DB4
FMC_I2C_SCL: R139.1 ; port FMC_I2C_SCL
FMC_I2C_SDA: R140.1 ; port FMC_I2C_SDA
GA0_FMC: J1.C34 R134.2 U21.1(A0)
GA1_FMC: J1.D35 R135.2 U21.2(A1)
PG-C2M: J1.D1 R137.2
PG-M2C: R137.1 ; port PG-M2C
SCL_I2C: U21.6(SCL) ; port SCL_I2C
SCL_Local: J1.C30 R139.2
SDA_I2C: U21.5(SDA) ; port SDA_I2C
SDA_Local: J1.C31 R140.2
TDI_FMC: J1.D30 R138.2
TDO_FMC: J1.D31 R138.1
NetJ1_B40: J1.B40 R145.2
NetR136_2: R136.2 U21.3(A2)

Not connected (* = marked no-connect by the designer): J1 A2 A3 A6 A7 A10 A11 A14 A15 A18 A19 A22 A23 A26 A27 A30 A31 A34 A35 A38 A39 B1 B4 B5 B8 B9 B12 B13 B16 B17 B20 B21 B24 B25 B28 B29 B32 B33 B36 B37 C2 C3 C6 C7 C11 C14 C15 C19 C22 C23 C26 C27 C39* D4 D5 D9 D12 D15 D18 D20 D21 D23 D24 D26 D27 D29 D33 D34 D36* D38* D40* E2 E3 E6 E7 E9 E10 E12 E13 E15 E16 E18 E19 E21 E22 E24 E25 E27 E28 E30 E31 E33 E34 E36 E37

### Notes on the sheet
- (near U21) EEPROM
- FPGA → I2C BUS

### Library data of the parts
C88 = capcc09401: as C80 on sheet DUT IO
J1 = ASP-134488-01: FMC, High Density Array, Male / EVM Connector 40x10; Manufacturer: Samtec; UniqueID: cmp00010; Pitch (mm): 1.27
R134-R136 = RSMD020101186: RES SMD 10K OHM 5% 1/20W 0201; Manufacturer: Panasonic Electronic Components; CompType: Resistor SMD; Power (Watts): 0.05W, 1/20W; Temperature Coefficient: ±200ppm/°C
R137-R140 = RSMD020101699: as R74 on sheet ADC Inputs
R145 = RSMD020100147: RES SMD 220 OHM 1% 1/20W 0201; Manufacturer: Panasonic Electronic Components; CompType: Resistor SMD; Power (Watts): 0.05W, 1/20W; Temperature Coefficient: ±200ppm/°C
U21 = cmp00154: EEPROM 64K 8KX8 1.8V SER EE IND 1/4AWP RPO; Manufacturer: Microchip

## Sheet FMC+ Sections F-H, J, K.SchDoc: FMC+ Section Rows F - H, J, K
size 431 x 279 mm; Date: Not shown in title block; ApprovedBy: Not shown in title block; CheckedBy: Not shown in title block; Author: Not shown in title block; CompanyName: Not shown in title block; Engineer: Not shown in title block; Organization: Not shown in title block; Address1: Not shown in title block; Address2: Not shown in title block; Address3: Not shown in title block; Address4: Not shown in title block; DocumentNumber: 3; Revision: Use project parameter SCH_Rev; SheetNumber: 12; SheetTotal: 15; PageSetup: Record=PageOptions¦CenterHorizontal=True¦CenterVertical=True¦PrintScale=1.00¦XCorrection=1.00¦YCorrection=1.00¦PrintKind=0¦BorderSize=5000000¦LeftOffset=0¦BottomOffset=0¦Orientation=2¦PaperLength=1000¦PaperWidth=1000¦Scale=100¦PaperSource=15¦PrintQuality=600¦MediaType=1¦DitherType=10¦PaperKind=Letter¦PrintScaleMode=1

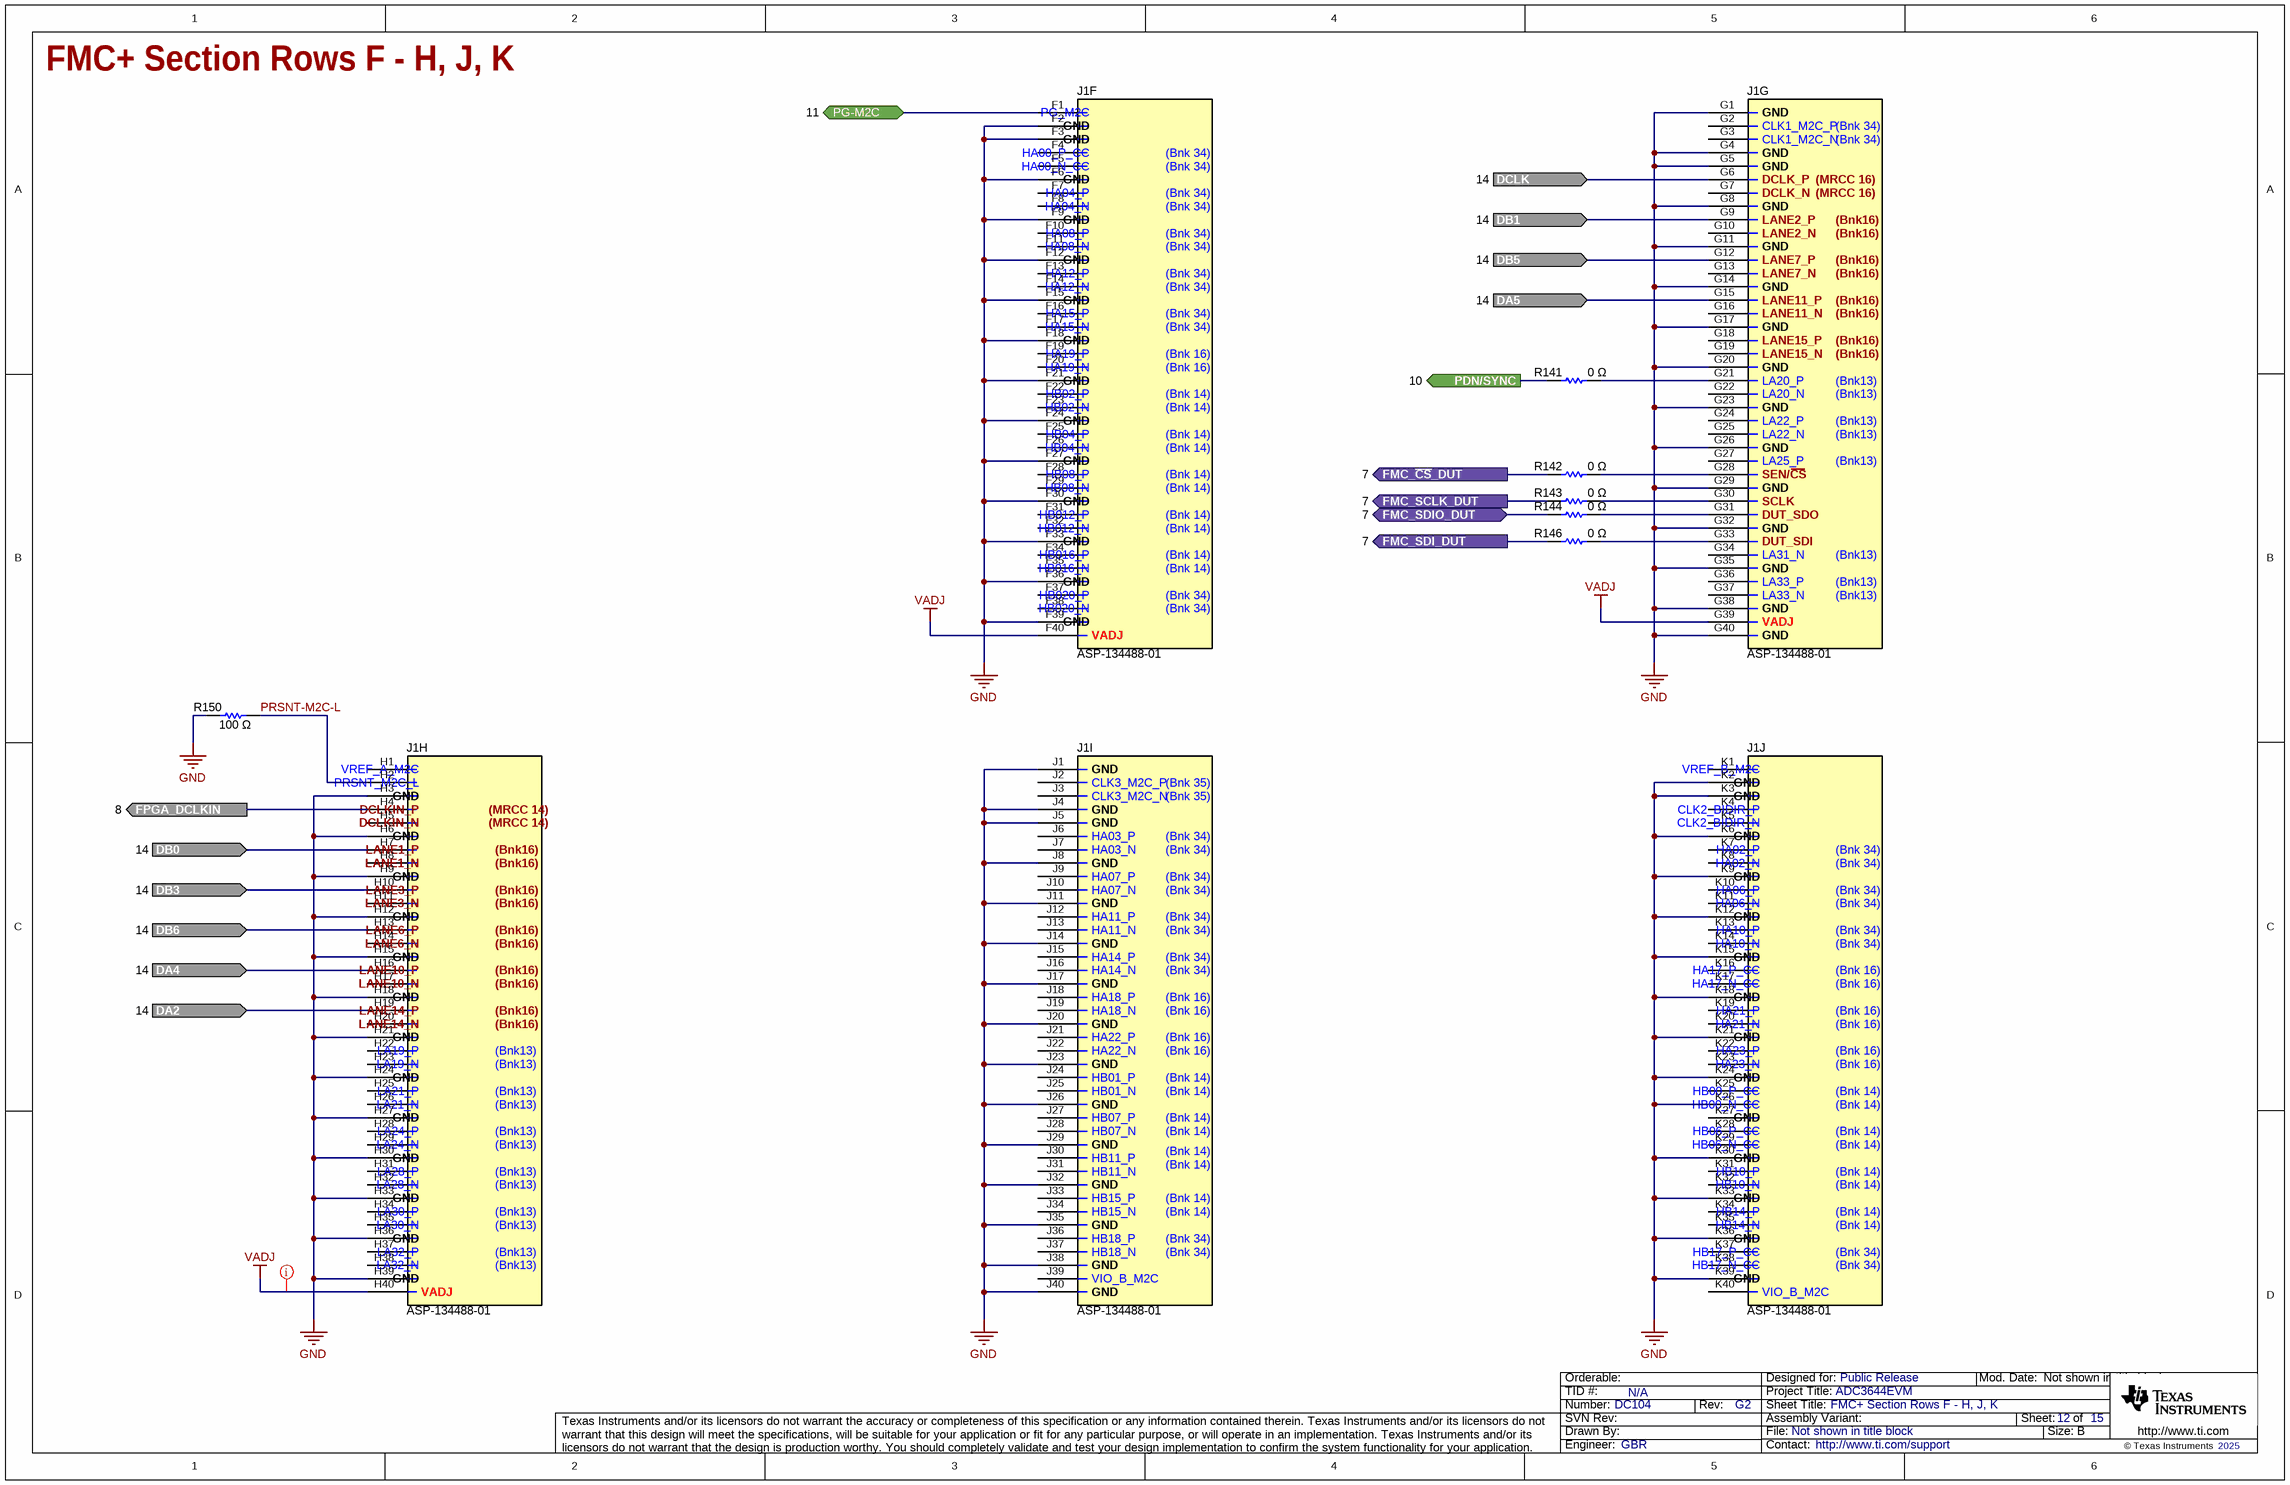
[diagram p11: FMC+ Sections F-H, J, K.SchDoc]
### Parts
J1  ASP-134488-01  [SAMTEC_ASP-134488-01]  (parts F,G,H,I,J of 10)
R141  value 0 Ω  [0201]  (hidden comment: ERJ-1GN0R00C)
R142  value 0 Ω  [0201]  (hidden comment: ERJ-1GN0R00C)
R143  value 0 Ω  [0201]  (hidden comment: ERJ-1GN0R00C)
R144  value 0 Ω  [0201]  (hidden comment: ERJ-1GN0R00C)
R146  value 0 Ω  [0201]  (hidden comment: ERJ-1GN0R00C)
R150  value 100 Ω  [0402L]  (hidden comment: ERJ-2RKF1000X)

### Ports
DA2 (in, see 14), DA4 (in, see 14), DA5 (in, see 14), DB0 (in, see 14), DB1 (in, see 14), DB3 (in, see 14), DB5 (in, see 14), DB6 (in, see 14), DCLK (in, see 14), FMC_SCLK_DUT (out, see 7), FMC_SDI_DUT (out, see 7), FMC_SDIO_DUT (bidir, see 7), FMC_~{CS}_DUT (out, see 7), FPGA_DCLKIN (out, see 8), PDN/SYNC (out, see 10), PG-M2C (bidir, see 11)

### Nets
GND: J1.F2 J1.F3 J1.F6 J1.F9 J1.F12 J1.F15 J1.F18 J1.F21 J1.F24 J1.F27 J1.F30 J1.F33 J1.F36 J1.F39 J1.G1 J1.G4 J1.G5 J1.G8 J1.G11 J1.G14 J1.G17 J1.G20 J1.G23 J1.G26 J1.G29 J1.G32 J1.G35 J1.G38 J1.G40 J1.H3 J1.H6 J1.H9 J1.H12 J1.H15 J1.H18 J1.H21 J1.H24 J1.H27 J1.H30 J1.H33 J1.H36 J1.H39 J1.J1 J1.J4 J1.J5 J1.J8 J1.J11 J1.J14 J1.J17 J1.J20 J1.J23 J1.J26 J1.J29 J1.J32 J1.J35 J1.J38 J1.J40 J1.K2 J1.K3 J1.K6 J1.K9 J1.K12 J1.K15 J1.K18 J1.K21 J1.K24 J1.K26 J1.K30 J1.K33 J1.K36 J1.K39 R150.1
VADJ: J1.F40 J1.G39 J1.H40
DA2: J1.H19 ; port DA2
DA4: J1.H16 ; port DA4
DA5: J1.G15 ; port DA5
DB0: J1.H7 ; port DB0
DB1: J1.G9 ; port DB1
DB3: J1.H10 ; port DB3
DB5: J1.G12 ; port DB5
DB6: J1.H13 ; port DB6
DCLK: J1.G6 ; port DCLK
FMC_~{CS}_DUT_LVLS: R142.1 ; port FMC_~{CS}_DUT
FMC_SCLK_DUT_LVLS: R143.1 ; port FMC_SCLK_DUT
FMC_SDI_DUT: R146.1 ; port FMC_SDI_DUT
FMC_SDO_DUT_LVLS: R144.1 ; port FMC_SDIO_DUT
FPGA_DCLKIN: J1.H4 ; port FPGA_DCLKIN
PDN/SYNC: R141.1 ; port PDN/SYNC
PG-M2C: J1.F1 ; port PG-M2C
PRSNT-M2C-L: J1.H2 R150.2
NetJ1_G21: J1.G21 R141.2
NetJ1_G28: J1.G28 R142.2
NetJ1_G30: J1.G30 R143.2
NetJ1_G31: J1.G31 R144.2
NetJ1_G33: J1.G33 R146.2

Not connected (* = marked no-connect by the designer): J1 F4 F5 F7 F8 F10 F11 F13 F14 F16 F17 F19 F20 F22 F23 F25 F26 F28 F29 F31 F32 F34 F35 F37 F38 G2 G3 G7 G10 G13 G16 G18 G19 G22 G24 G25 G27 G34 G36 G37 H1 H5 H8 H11 H14 H17 H20 H22 H23 H25 H26 H28 H29 H31 H32 H34 H35 H37 H38 J2 J3 J6 J7 J9 J10 J12 J13 J15 J16 J18 J19 J21 J22 J24 J25 J27 J28 J30 J31 J33 J34 J36 J37 J39 K1 K4 K5 K7 K8 K10 K11 K13 K14 K16 K17 K19 K20 K22 K23 K25 K27 K28 K29 K31 K32 K34 K35 K37 K38 K40

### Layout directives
net class Power; net class FMCPwr: VADJ

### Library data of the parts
J1 = ASP-134488-01: as J1 on sheet FMC+ Sections A-E
R141-R144 R146 = RSMD020101699: as R74 on sheet ADC Inputs
R150 = RSMD040200375: RES SMD 100 OHM 1% 1/10W 0402; Manufacturer: Panasonic Electronic Components; CompType: Resistor SMD; Power (Watts): 0.1W, 1/10W; Temperature Coefficient: ±100ppm/°C; SizeX_mm: 1; SizeY_mm: 0.5; SizeZ_mm: 0.4

## Sheet Ouptut Buffer.SchDoc: Output Buffer
size 431 x 279 mm; Date: Not shown in title block; ApprovedBy: Not shown in title block; CheckedBy: Not shown in title block; Author: Not shown in title block; CompanyName: Not shown in title block; Engineer: Not shown in title block; Organization: Not shown in title block; Address1: Not shown in title block; Address2: Not shown in title block; Address3: Not shown in title block; Address4: Not shown in title block; DocumentNumber: 1; Revision: Use project parameter SCH_Rev; SheetNumber: 13; SheetTotal: 15; PageSetup: Record=PageOptions¦CenterHorizontal=True¦CenterVertical=True¦PrintScale=1.00¦XCorrection=1.00¦YCorrection=1.00¦PrintKind=0¦BorderSize=5000000¦LeftOffset=0¦BottomOffset=0¦Orientation=2¦PaperLength=1000¦PaperWidth=1000¦Scale=100¦PaperSource=15¦PrintQuality=600¦MediaType=1¦DitherType=10¦PaperKind=Letter¦PrintScaleMode=1

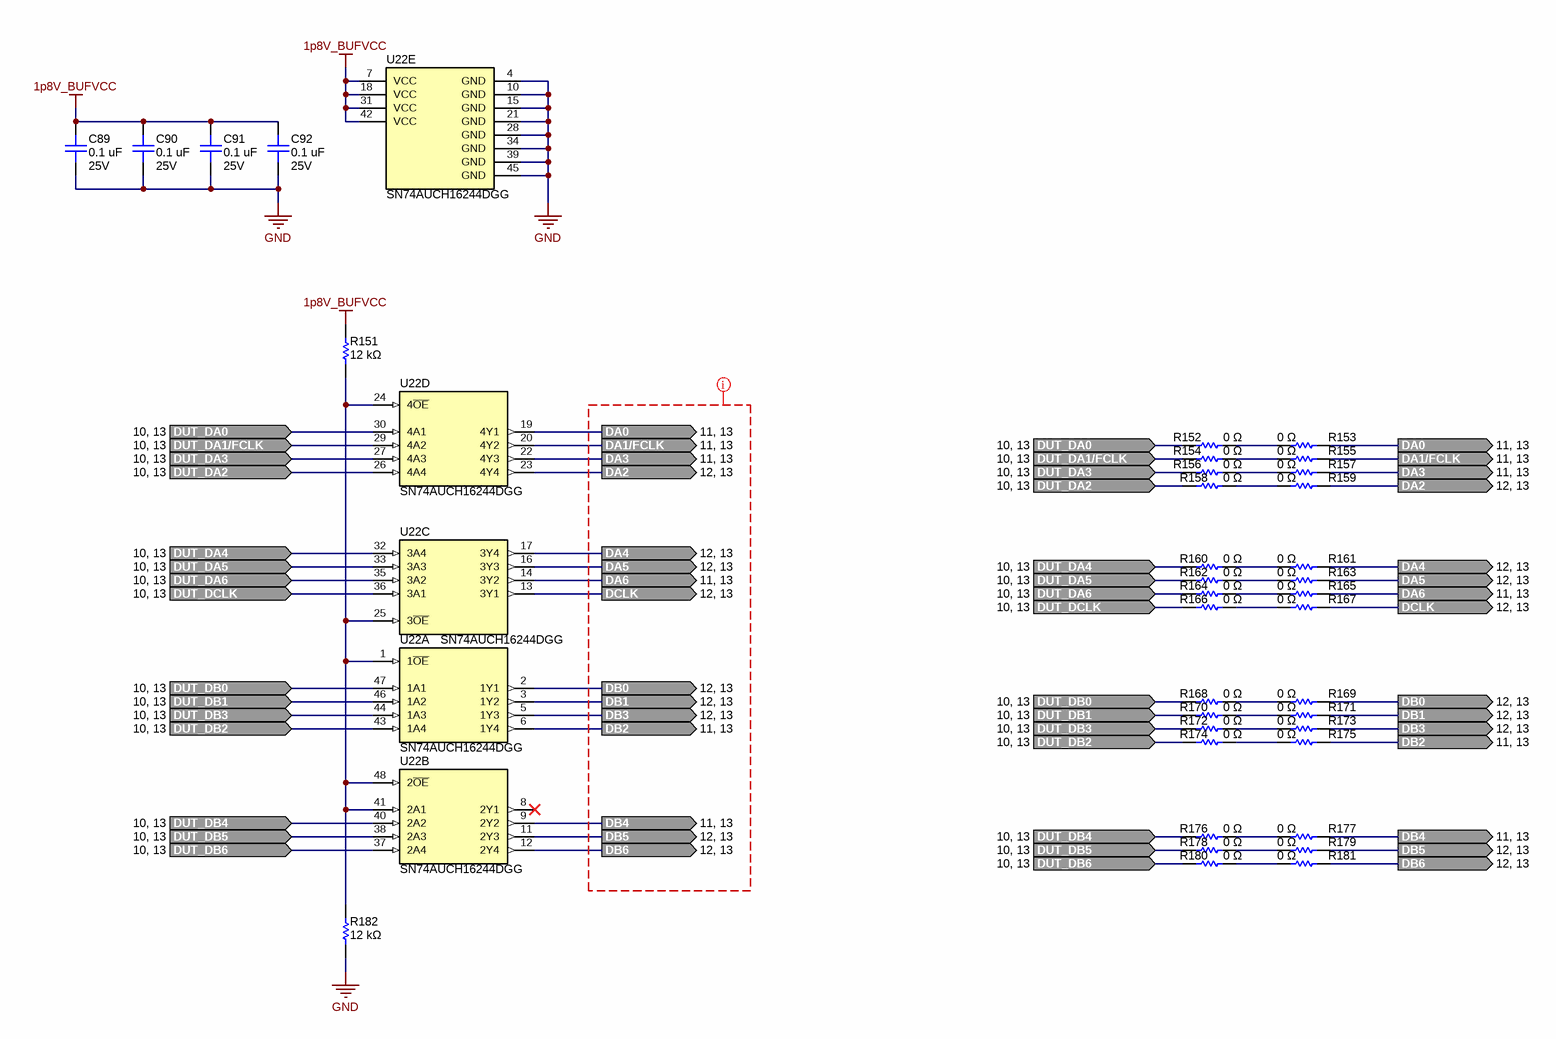
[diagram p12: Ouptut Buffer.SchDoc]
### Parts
C89  value 0.1 uF  Voltage - Rated: 25V  [0402L_cap]  (hidden comment: GRT155R71E104KE01J)
C90  value 0.1 uF  Voltage - Rated: 25V  [0402L_cap]  (hidden comment: GRT155R71E104KE01J)
C91  value 0.1 uF  Voltage - Rated: 25V  [0402L_cap]  (hidden comment: GRT155R71E104KE01J)
C92  value 0.1 uF  Voltage - Rated: 25V  [0402L_cap]  (hidden comment: GRT155R71E104KE01J)
R151  value 12 kΩ  [0201]  (hidden comment: ERJ-1GNJ123C)
R152  value 0 Ω  [0201]  (hidden comment: ERJ-1GN0R00C)
R153  value 0 Ω  [0201]  (hidden comment: ERJ-1GN0R00C)
R154  value 0 Ω  [0201]  (hidden comment: ERJ-1GN0R00C)
R155  value 0 Ω  [0201]  (hidden comment: ERJ-1GN0R00C)
R156  value 0 Ω  [0201]  (hidden comment: ERJ-1GN0R00C)
R157  value 0 Ω  [0201]  (hidden comment: ERJ-1GN0R00C)
R158  value 0 Ω  [0201]  (hidden comment: ERJ-1GN0R00C)
R159  value 0 Ω  [0201]  (hidden comment: ERJ-1GN0R00C)
R160  value 0 Ω  [0201]  (hidden comment: ERJ-1GN0R00C)
R161  value 0 Ω  [0201]  (hidden comment: ERJ-1GN0R00C)
R162  value 0 Ω  [0201]  (hidden comment: ERJ-1GN0R00C)
R163  value 0 Ω  [0201]  (hidden comment: ERJ-1GN0R00C)
R164  value 0 Ω  [0201]  (hidden comment: ERJ-1GN0R00C)
R165  value 0 Ω  [0201]  (hidden comment: ERJ-1GN0R00C)
R166  value 0 Ω  [0201]  (hidden comment: ERJ-1GN0R00C)
R167  value 0 Ω  [0201]  (hidden comment: ERJ-1GN0R00C)
R168  value 0 Ω  [0201]  (hidden comment: ERJ-1GN0R00C)
R169  value 0 Ω  [0201]  (hidden comment: ERJ-1GN0R00C)
R170  value 0 Ω  [0201]  (hidden comment: ERJ-1GN0R00C)
R171  value 0 Ω  [0201]  (hidden comment: ERJ-1GN0R00C)
R172  value 0 Ω  [0201]  (hidden comment: ERJ-1GN0R00C)
R173  value 0 Ω  [0201]  (hidden comment: ERJ-1GN0R00C)
R174  value 0 Ω  [0201]  (hidden comment: ERJ-1GN0R00C)
R175  value 0 Ω  [0201]  (hidden comment: ERJ-1GN0R00C)
R176  value 0 Ω  [0201]  (hidden comment: ERJ-1GN0R00C)
R177  value 0 Ω  [0201]  (hidden comment: ERJ-1GN0R00C)
R178  value 0 Ω  [0201]  (hidden comment: ERJ-1GN0R00C)
R179  value 0 Ω  [0201]  (hidden comment: ERJ-1GN0R00C)
R180  value 0 Ω  [0201]  (hidden comment: ERJ-1GN0R00C)
R181  value 0 Ω  [0201]  (hidden comment: ERJ-1GN0R00C)
R182  value 12 kΩ  [0201]  (hidden comment: ERJ-1GNJ123C)
U22  SN74AUCH16244DGG  [DGG0048A]  (parts A,B,C,D,E of 5)

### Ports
DA0 (out, see 11, 13), DA1/FCLK (out, see 11, 13), DA2 (out, see 12, 13), DA3 (out, see 11, 13), DA4 (out, see 12, 13), DA5 (out, see 12, 13), DA6 (out, see 11, 13), DB0 (out, see 12, 13), DB1 (out, see 12, 13), DB2 (out, see 11, 13), DB3 (out, see 12, 13), DB4 (out, see 11, 13), DB5 (out, see 12, 13), DB6 (out, see 12, 13), DCLK (out, see 12, 13), DUT_DA0 (in, see 10, 13), DUT_DA1/FCLK (in, see 10, 13), DUT_DA2 (in, see 10, 13), DUT_DA3 (in, see 10, 13), DUT_DA4 (in, see 10, 13), DUT_DA5 (in, see 10, 13), DUT_DA6 (in, see 10, 13), DUT_DB0 (in, see 10, 13), DUT_DB1 (in, see 10, 13), DUT_DB2 (in, see 10, 13), DUT_DB3 (in, see 10, 13), DUT_DB4 (in, see 10, 13), DUT_DB5 (in, see 10, 13), DUT_DB6 (in, see 10, 13), DUT_DCLK (in, see 10, 13)

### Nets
1p8V_BUFVCC: C89.2 C90.2 C91.2 C92.2 R151.2 U22.7(VCC) U22.18(VCC) U22.31(VCC) U22.42(VCC)
GND: C89.1 C90.1 C91.1 C92.1 R182.1 U22.4(GND) U22.10(GND) U22.15(GND) U22.21(GND) U22.28(GND) U22.34(GND) U22.39(GND) U22.45(GND)
DA0: R153.2 U22.19(4Y1) ; port DA0
DA1/FCLK: R155.2 U22.20(4Y2) ; port DA1/FCLK
DA2: R159.2 U22.23(4Y4) ; port DA2
DA3: R157.2 U22.22(4Y3) ; port DA3
DA4: R161.2 U22.17(3Y4) ; port DA4
DA5: R163.2 U22.16(3Y3) ; port DA5
DA6: R165.2 U22.14(3Y2) ; port DA6
DB0: R169.2 U22.2(1Y1) ; port DB0
DB1: R171.2 U22.3(1Y2) ; port DB1
DB2: R175.2 U22.6(1Y4) ; port DB2
DB3: R173.2 U22.5(1Y3) ; port DB3
DB4: R177.2 U22.9(2Y2) ; port DB4
DB5: R179.2 U22.11(2Y3) ; port DB5
DB6: R181.2 U22.12(2Y4) ; port DB6
DCLK: R167.2 U22.13(3Y1) ; port DCLK
DUT_DA0: R152.1 U22.30(4A1) ; port DUT_DA0
DUT_DA1/FCLK: R154.1 U22.29(4A2) ; port DUT_DA1/FCLK
DUT_DA2: R158.1 U22.26(4A4) ; port DUT_DA2
DUT_DA3: R156.1 U22.27(4A3) ; port DUT_DA3
DUT_DA4: R160.1 U22.32(3A4) ; port DUT_DA4
DUT_DA5: R162.1 U22.33(3A3) ; port DUT_DA5
DUT_DA6: R164.1 U22.35(3A2) ; port DUT_DA6
DUT_DB0: R168.1 U22.47(1A1) ; port DUT_DB0
DUT_DB1: R170.1 U22.46(1A2) ; port DUT_DB1
DUT_DB2: R174.1 U22.43(1A4) ; port DUT_DB2
DUT_DB3: R172.1 U22.44(1A3) ; port DUT_DB3
DUT_DB4: R176.1 U22.40(2A2) ; port DUT_DB4
DUT_DB5: R178.1 U22.38(2A3) ; port DUT_DB5
DUT_DB6: R180.1 U22.37(2A4) ; port DUT_DB6
DUT_DCLK: R166.1 U22.36(3A1) ; port DUT_DCLK
NetR151_1: R151.1 R182.2 U22.1(1~{OE}) U22.24(4~{OE}) U22.25(3~{OE}) U22.41(2A1) U22.48(2~{OE})
NetR152_2: R152.2 R153.1
NetR154_2: R154.2 R155.1
NetR156_2: R156.2 R157.1
NetR158_2: R158.2 R159.1
NetR160_2: R160.2 R161.1
NetR162_2: R162.2 R163.1
NetR164_2: R164.2 R165.1
NetR166_2: R166.2 R167.1
NetR168_2: R168.2 R169.1
NetR170_2: R170.2 R171.1
NetR172_2: R172.2 R173.1
NetR174_2: R174.2 R175.1
NetR176_2: R176.2 R177.1
NetR178_2: R178.2 R179.1
NetR180_2: R180.2 R181.1

Not connected (* = marked no-connect by the designer): U22 8(2Y1)*

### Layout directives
net class CMOS_BUF_Out: (no net found under the mark)

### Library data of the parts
C89-C92 = capcc09401: as C80 on sheet DUT IO
R151 R182 = RSMD020101206: RES SMD 12K OHM 5% 1/20W 0201; Manufacturer: Panasonic Electronic Components; CompType: Resistor SMD; Power (Watts): 0.05W, 1/20W; Temperature Coefficient: ±200ppm/°C
R152-R181 = RSMD020101699: as R74 on sheet ADC Inputs
U22 = SN74AUCH16244DGG: 16-ch, 0.8-V to 2.7-V high speed buffers with bus-hold and 3-state outputs; Manufacturer: Texas Instruments; CompType: Buffer

## Sheet Hardware & Mechanicals.SchDoc: Hardware & Mechanicals
size 431 x 279 mm; Date: Not shown in title block; ApprovedBy: Not shown in title block; CheckedBy: Not shown in title block; Author: Not shown in title block; CompanyName: Not shown in title block; Engineer: Not shown in title block; Organization: Not shown in title block; Address1: Not shown in title block; Address2: Not shown in title block; Address3: Not shown in title block; Address4: Not shown in title block; DocumentNumber: 4; Revision: Use project parameter SCH_Rev; SheetNumber: 13; SheetTotal: 14; PageSetup: Record=PageOptions¦CenterHorizontal=True¦CenterVertical=True¦PrintScale=1.00¦XCorrection=1.00¦YCorrection=1.00¦PrintKind=0¦BorderSize=5000000¦LeftOffset=0¦BottomOffset=0¦Orientation=2¦PaperLength=1000¦PaperWidth=1000¦Scale=100¦PaperSource=15¦PrintQuality=600¦MediaType=1¦DitherType=10¦PaperKind=Letter¦PrintScaleMode=1

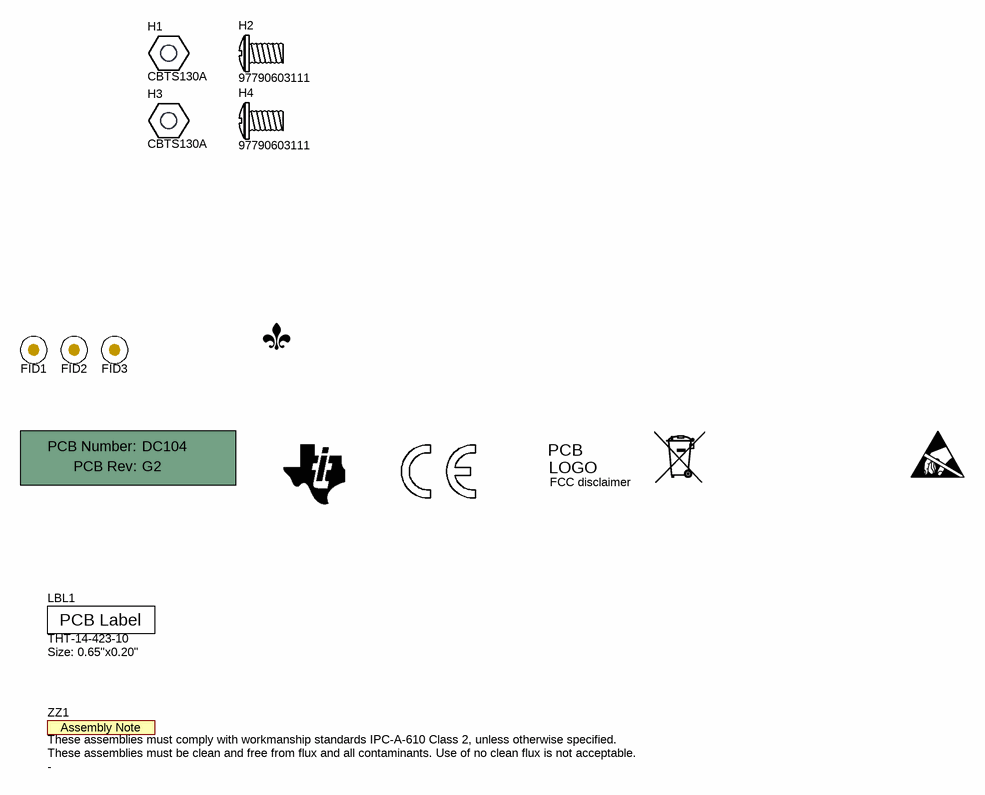
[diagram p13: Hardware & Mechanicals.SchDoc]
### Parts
!PCB1  (no value)  (mechanical)
FID1  Fiducial Mark  [Fiducial10-20]  (value not drawn)  (no BOM)
FID2  Fiducial Mark  [Fiducial10-20]  (value not drawn)  (no BOM)
FID3  Fiducial Mark  [Fiducial10-20]  (value not drawn)  (no BOM)
H1  CBTS130A  [cbts130a]
H2  97790603111  [97790603111]  (mechanical)
H3  CBTS130A  [cbts130a]
H4  97790603111  [97790603111]  (mechanical)
LBL1  THT-14-423-10  Text1: Size: 0.65"x0.20"  [Label_650x200]
Logo1  FDL Logo  [FDL_Small]  (value not drawn)  (no BOM)
Logo2  FCC disclaimer  [FCC_disclaimer]  (no BOM)
Logo3  ESD Overlay  [ESD_Overlay_Small]  (value not drawn)  (no BOM)
Logo4  WEEE  [WEEE_Minimum]  (value not drawn)  (no BOM)
LOGO5  CE Mark  [CE_Mark_5mm]  (value not drawn)  (no BOM)
Logo6  Texas Instruments  [TI_Stacked_Overlay_Small_Vertical]  (value not drawn)  (no BOM)
ZZ1  Text3: These assemblies must comply with workmanship standards IPC-A-610 Class 2, unless otherwise specified.  Text2: These assemblies must be clean and free from flux and all contaminants. Use of no clean flux is not acceptable.  [AssemblyNote]  (hidden comment: These assemblies are ESD sensitive, ESD precautions shall be observed.)  (no BOM)

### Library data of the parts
!PCB1 = cmp00109: Printed Circuit Board; CompType: PCB
FID1-FID3 = cmp00099: Fiducial; SymbolCreator: a0412235
H1 H3 = CBTS130A: Hex Standoff Threaded M3 Nylon 1.260" (32.00mm) Natural; Manufacturer: Essentra Components; UniqueID: CBTS010A
H2 H4 = 97790603111: M3 Pan Head Machine Screw Phillips Drive Nylon; Manufacturer: Murth Elektronik
LBL1 = cmp00106: Thermal Transfer Printable Labels, 0.650" W x 0.200" H - 10,000 per roll; Manufacturer: Brady; CompType: Label
Logo1 = cmp00105: FDL
Logo2 = cmp00102: FCC_disclaimer; CompType: Logo
Logo3 = cmp00317: PartNumber: ESD Logo; CompType: Logo
Logo4 = cmp00101: CompType: Logo
LOGO5 = cmp00103: CE_Mark; CompType: Logo
Logo6 = cmp00104: Texas Instrument Corporate Signature; PartNumber: TI Bug; CompType: Logo
ZZ1 = cmp00108: Assembly Notes

## Sheet Revision History.SchDoc: Rev History & Variants
size 431 x 279 mm; Date: Not shown in title block; ApprovedBy: Not shown in title block; CheckedBy: Not shown in title block; Author: Not shown in title block; CompanyName: Not shown in title block; Engineer: Not shown in title block; Organization: Not shown in title block; Address1: Not shown in title block; Address2: Not shown in title block; Address3: Not shown in title block; Address4: Not shown in title block; DocumentNumber: 5; Revision: Use project parameter SCH_Rev; SheetNumber: 15; SheetTotal: 15; PageSetup: Record=PageOptions¦CenterHorizontal=True¦CenterVertical=True¦PrintScale=1.00¦XCorrection=1.00¦YCorrection=1.00¦PrintKind=0¦BorderSize=5000000¦LeftOffset=0¦BottomOffset=0¦Orientation=2¦PaperLength=1000¦PaperWidth=1000¦Scale=100¦PaperSource=15¦PrintQuality=600¦MediaType=1¦DitherType=10¦PaperKind=Letter¦PrintScaleMode=1

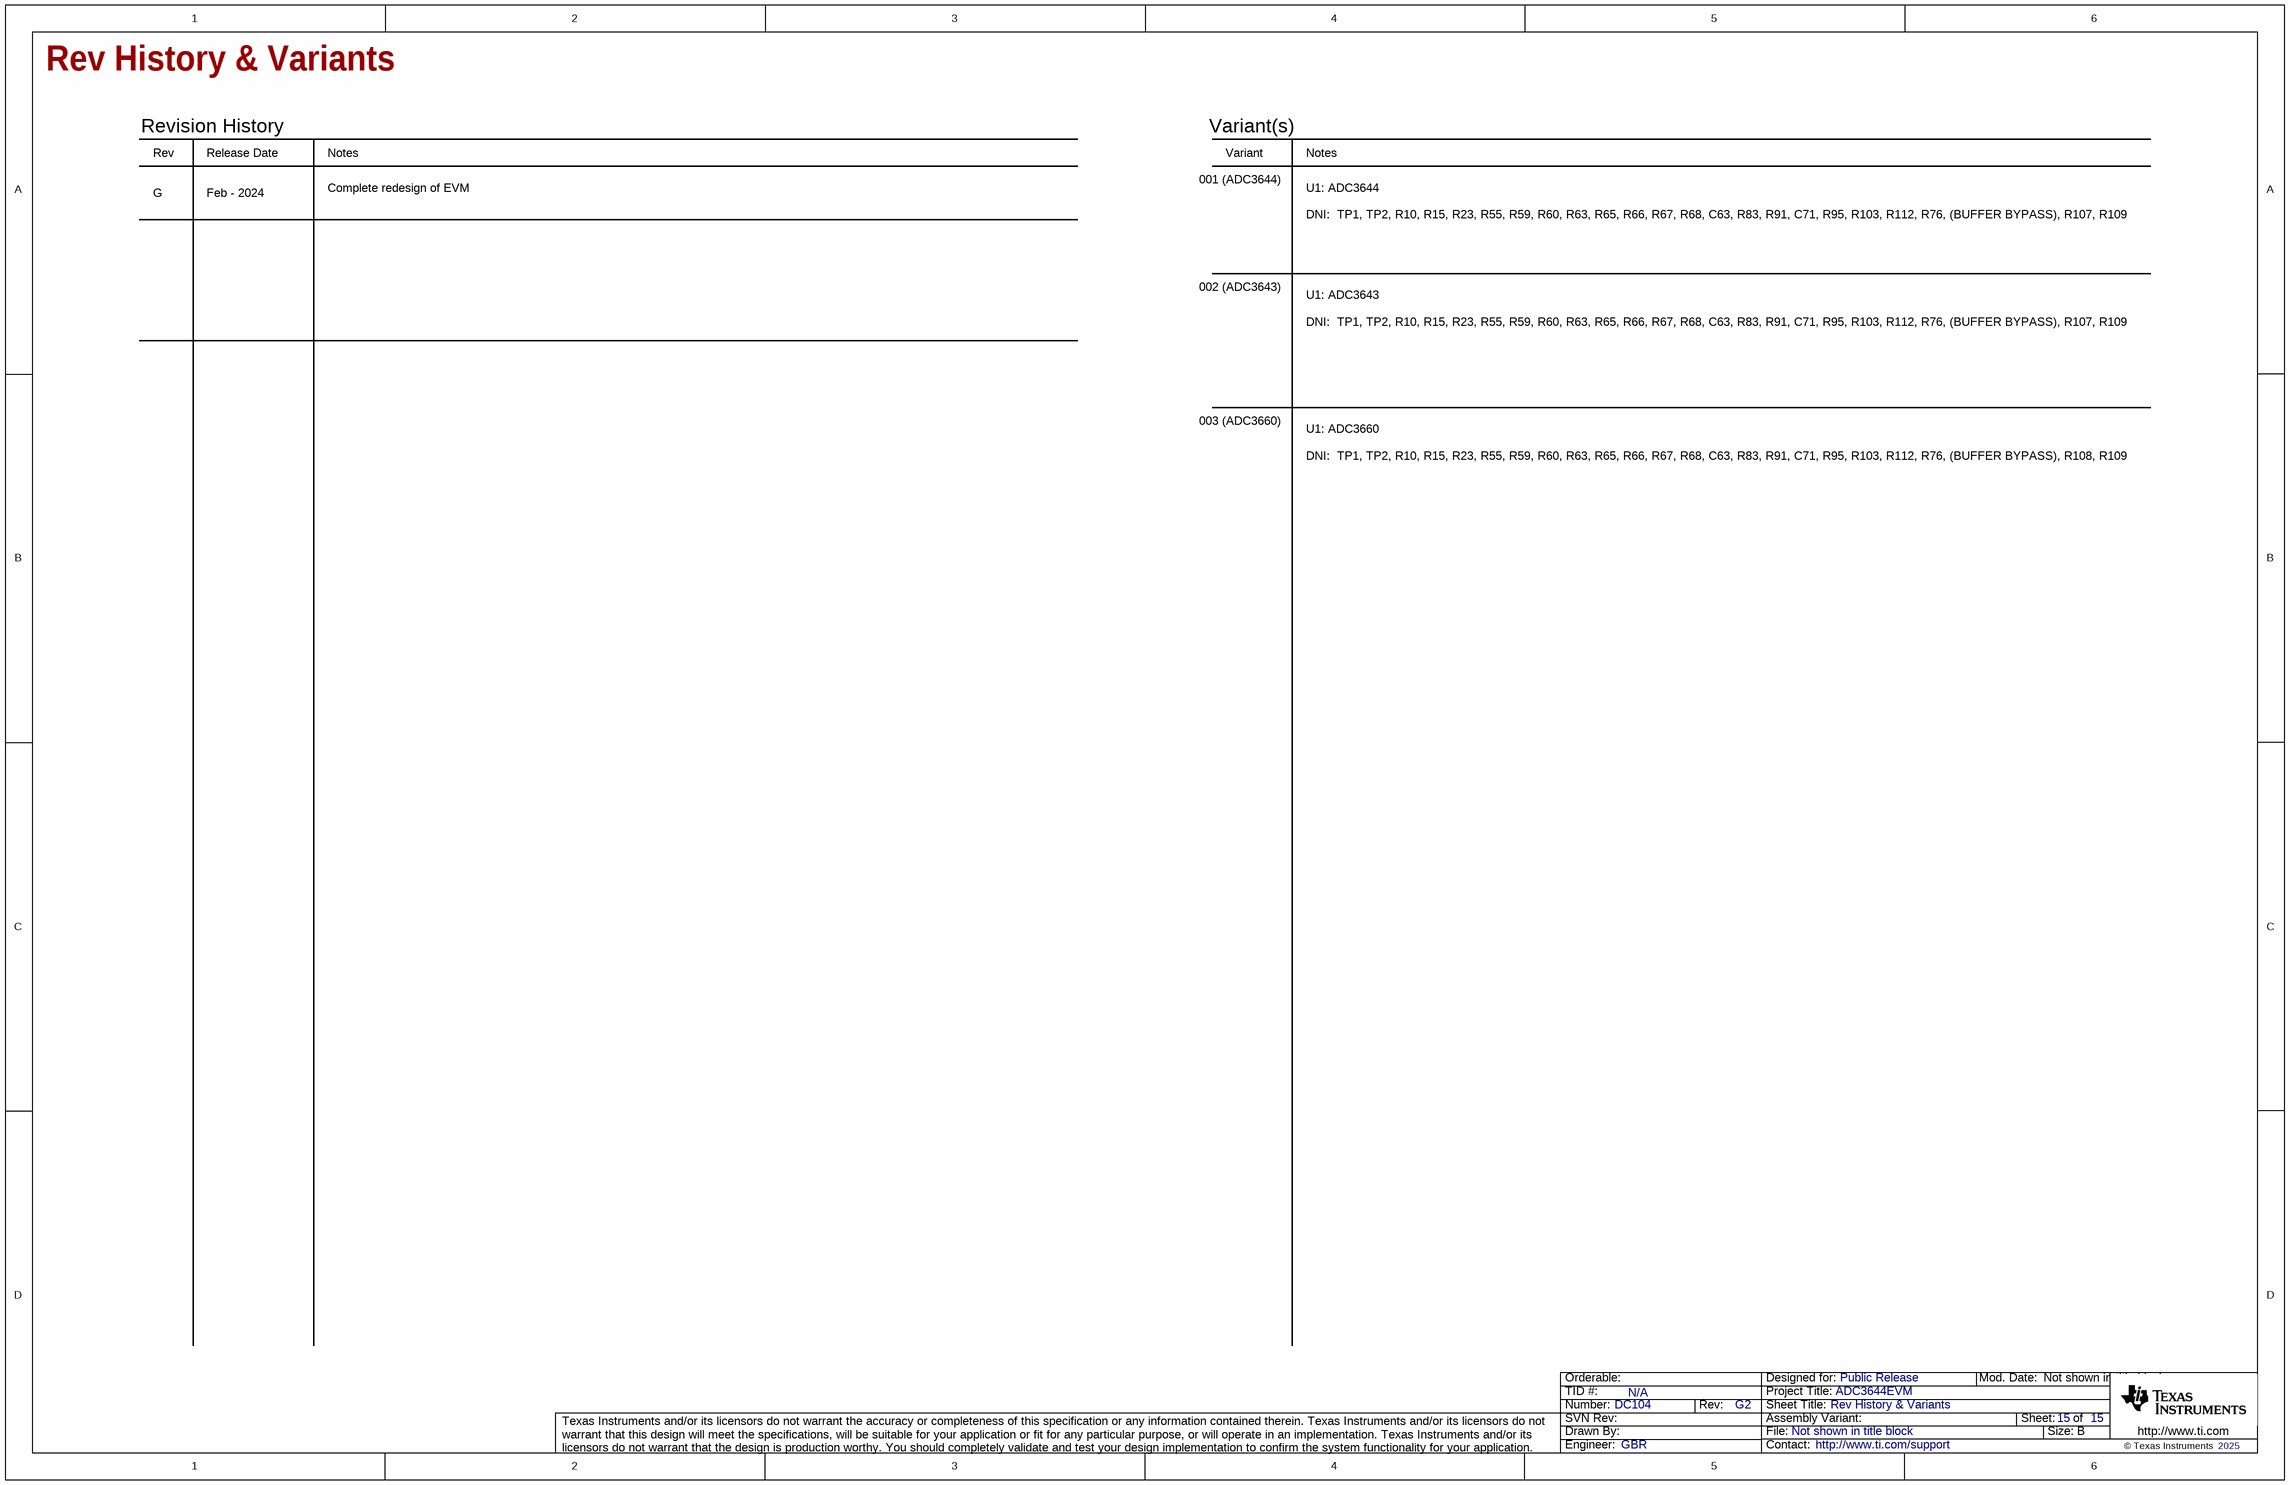
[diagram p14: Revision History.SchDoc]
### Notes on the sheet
- Rev
- Release Date
- Revision History
- Notes
- Variant
- Variant(s)
- G
- Feb - 2024
- Complete redesign of EVM
- 001 (ADC3644)
- 002 (ADC3643)
- U1: ADC3644
  DNI:  TP1, TP2, R10, R15, R23, R55, R59, R60, R63, R65, R66, R67, R68, C63, R83, R91, C71, R95, R103, R112, R76, (BUFFER BYPASS), R107, R109
- U1: ADC3643
  DNI:  TP1, TP2, R10, R15, R23, R55, R59, R60, R63, R65, R66, R67, R68, C63, R83, R91, C71, R95, R103, R112, R76, (BUFFER BYPASS), R107, R109
- 003 (ADC3660)
- U1: ADC3660
  DNI:  TP1, TP2, R10, R15, R23, R55, R59, R60, R63, R65, R66, R67, R68, C63, R83, R91, C71, R95, R103, R112, R76, (BUFFER BYPASS), R108, R109

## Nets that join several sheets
1p8V_AVDD: Power LDO (C21.2 FB2.2 PP3.1), Power Sense ADC (U9.8), DUT IO (6 pins)
1p8V_BUFVCC: Power LDO (C93.2 FC1.3), Ouptut Buffer (9 pins)
1p8V_IOVDD: Power LDO (C27.2 FB3.2 PP4.1), Power Sense ADC (U9.4), DUT IO (C76.2 C77.2 U1.21 U1.30)
1p8V_LVLSHIFT: Power LDO (7 pins), Comms LVL Shift and MUX (9 pins), CLK and DCLKIN (R70.2), DUT IO (7 pins)
2p3V: Power DC-DC (5 pins), Power LDO (10 pins)
3p3V_Utility: 12V Input, Efuse and 3p3V Utility (6 pins), Power DC-DC (R10.2), Power LDO (6 pins), Power Sense ADC (6 pins), USB Control FTDI (24 pins), Comms LVL Shift and MUX (13 pins), CLK and DCLKIN (C55.2 R73.2 U17.10), DUT IO (C85.2 R131.2 U20.4)
12V: 12V Input, Efuse and 3p3V Utility (10 pins), Power DC-DC (C9.2 C10.2 R11.2 U4.18), Power LDO (D4.1 D5.1)
12V_FMC: 12V Input, Efuse and 3p3V Utility (SW1.3), FMC+ Sections A-E (J1.C35 J1.C37)
GND: 12V Input, Efuse and 3p3V Utility (16 pins), Power DC-DC (24 pins), Power LDO (26 pins), Power Sense ADC (7 pins), USB Control FTDI (32 pins), Comms LVL Shift and MUX (20 pins), CLK and DCLKIN (22 pins), ADC Inputs (24 pins), DUT IO (35 pins), FMC+ Sections A-E (96 pins), FMC+ Sections F-H, J, K (72 pins), Ouptut Buffer (13 pins)
VADJ: FMC+ Sections A-E (J1.E39), FMC+ Sections F-H, J, K (J1.F40 J1.G39 J1.H40)
VCM: ADC Inputs (6 pins), DUT IO (C78.2 C79.2 TP3.1 U1.8)
3p3VU_PG: 12V Input, Efuse and 3p3V Utility (R5.1 U3.7), Power DC-DC (R9.2)
AIN_N: ADC Inputs (R85.2), DUT IO (U1.13)
AIN_P: ADC Inputs (R77.2), DUT IO (U1.12)
BIN_N: ADC Inputs (R89.2), DUT IO (U1.38)
BIN_P: ADC Inputs (R97.2), DUT IO (U1.39)
CLK_N: CLK and DCLKIN (C54.2 R66.1), DUT IO (U1.7)
CLK_P: CLK and DCLKIN (C48.2 R66.2), DUT IO (U1.6)
DA0: FMC+ Sections A-E (J1.D17), Ouptut Buffer (R153.2 U22.19)
DA1/FCLK: FMC+ Sections A-E (J1.D8), Ouptut Buffer (R155.2 U22.20)
DA2: FMC+ Sections F-H, J, K (J1.H19), Ouptut Buffer (R159.2 U22.23)
DA3: FMC+ Sections A-E (J1.C18), Ouptut Buffer (R157.2 U22.22)
DA4: FMC+ Sections F-H, J, K (J1.H16), Ouptut Buffer (R161.2 U22.17)
DA5: FMC+ Sections F-H, J, K (J1.G15), Ouptut Buffer (R163.2 U22.16)
DA6: FMC+ Sections A-E (J1.D14), Ouptut Buffer (R165.2 U22.14)
DB0: FMC+ Sections F-H, J, K (J1.H7), Ouptut Buffer (R169.2 U22.2)
DB1: FMC+ Sections F-H, J, K (J1.G9), Ouptut Buffer (R171.2 U22.3)
DB2: FMC+ Sections A-E (J1.C10), Ouptut Buffer (R175.2 U22.6)
DB3: FMC+ Sections F-H, J, K (J1.H10), Ouptut Buffer (R173.2 U22.5)
DB4: FMC+ Sections A-E (J1.D11), Ouptut Buffer (R177.2 U22.9)
DB5: FMC+ Sections F-H, J, K (J1.G12), Ouptut Buffer (R179.2 U22.11)
DB6: FMC+ Sections F-H, J, K (J1.H13), Ouptut Buffer (R181.2 U22.12)
DC-DC_PG: Power DC-DC (R10.1 U4.19), Power LDO (R23.2)
DCLK: FMC+ Sections F-H, J, K (J1.G6), Ouptut Buffer (R167.2 U22.13)
DCLKIN: CLK and DCLKIN (U17.8), DUT IO (R127.1)
DUT_DA0: DUT IO (R99.2), Ouptut Buffer (R152.1 U22.30)
DUT_DA1/FCLK: DUT IO (R100.2), Ouptut Buffer (R154.1 U22.29)
DUT_DA2: DUT IO (R102.2), Ouptut Buffer (R158.1 U22.26)
DUT_DA3: DUT IO (R103.2), Ouptut Buffer (R156.1 U22.27)
DUT_DA4: DUT IO (R104.2), Ouptut Buffer (R160.1 U22.32)
DUT_DA5: DUT IO (R105.2), Ouptut Buffer (R162.1 U22.33)
DUT_DA6: DUT IO (R106.2), Ouptut Buffer (R164.1 U22.35)
DUT_DB0: DUT IO (R111.2), Ouptut Buffer (R168.1 U22.47)
DUT_DB1: DUT IO (R123.1), Ouptut Buffer (R170.1 U22.46)
DUT_DB2: DUT IO (R113.2), Ouptut Buffer (R174.1 U22.43)
DUT_DB3: DUT IO (R114.2), Ouptut Buffer (R172.1 U22.44)
DUT_DB4: DUT IO (R115.2), Ouptut Buffer (R176.1 U22.40)
DUT_DB5: DUT IO (R116.2), Ouptut Buffer (R178.1 U22.38)
DUT_DB6: DUT IO (R117.2), Ouptut Buffer (R180.1 U22.37)
DUT_DCLK: DUT IO (R98.2), Ouptut Buffer (R166.1 U22.36)
FMC_~{CS}_DUT_LVLS: Comms LVL Shift and MUX (R60.1 U15.4), FMC+ Sections F-H, J, K (R142.1)
FMC_I2C_SCL: Comms LVL Shift and MUX (U13.4), FMC+ Sections A-E (R139.1)
FMC_I2C_SDA: Comms LVL Shift and MUX (U13.2), FMC+ Sections A-E (R140.1)
FMC_SCLK_DUT_LVLS: Comms LVL Shift and MUX (R59.1 U15.1), FMC+ Sections F-H, J, K (R143.1)
FMC_SDI_DUT: Comms LVL Shift and MUX (R147.2 U23.1), FMC+ Sections F-H, J, K (R146.1)
FMC_SDO_DUT_LVLS: Comms LVL Shift and MUX (5 pins), FMC+ Sections F-H, J, K (R144.1)
FPGA_DCLKIN: CLK and DCLKIN (U17.3), FMC+ Sections F-H, J, K (J1.H4)
FTDI_CSb_SHIFT: USB Control FTDI (U11.17), Comms LVL Shift and MUX (R53.1 U14.4)
FTDI_I2C_SCL: USB Control FTDI (R35.2 U10.3), Comms LVL Shift and MUX (U13.7)
FTDI_SCLK_SHIFT: USB Control FTDI (R36.2), Comms LVL Shift and MUX (R52.1 U14.3)
FTDI_SDI_SHIFT: USB Control FTDI (U11.19), Comms LVL Shift and MUX (R54.1 U14.6)
FTDI_SDO_SHIFT: USB Control FTDI (U11.18), Comms LVL Shift and MUX (U14.5)
IOVDD_PG: Power LDO (Q3.1 R24.1 U8.4), DUT IO (U19.1)
ISENSE_AVDD: Power LDO (U5.4), Power Sense ADC (U9.9)
ISENSE_IOVDD: Power LDO (U7.4), Power Sense ADC (U9.5)
PDN/SYNC: DUT IO (J12.3), FMC+ Sections F-H, J, K (R141.1)
PG-M2C: FMC+ Sections A-E (R137.1), FMC+ Sections F-H, J, K (J1.F1)
SCL_I2C: Power Sense ADC (U9.14), Comms LVL Shift and MUX (PP6.1 U13.6), FMC+ Sections A-E (U21.6)
SCLK_DUT: Comms LVL Shift and MUX (PP7.1 U15.2), DUT IO (R125.1)
SDA_I2C: Power Sense ADC (U9.13), Comms LVL Shift and MUX (PP5.1 U13.10), FMC+ Sections A-E (U21.5)
SDIO_DUT: Comms LVL Shift and MUX (PP9.1 U15.7), DUT IO (R126.1)
SEN_DUT: Comms LVL Shift and MUX (PP8.1 U15.5), DUT IO (R129.1)
USB_I2C_SDAr: USB Control FTDI (R38.2 R40.2 U11.28), Comms LVL Shift and MUX (U13.9)

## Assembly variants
003 (ADC3660): not fitted C57 C65 C80 FID1 FID2 FID3 R10 R15 R23 R58 R62 R63 R66 R68 R69 R74 R76 R82 R86 R94 R108 R109 R120 R121 R123 TP1 TP2 U22; alternate parts U1 -> ADC3660IRSB
002 (ADC3643): not fitted C57 C65 C80 FID1 FID2 FID3 R10 R15 R23 R58 R62 R63 R66 R68 R69 R74 R76 R82 R86 R94 R107 R108 R120 R121 R123 TP1 TP2 U22; alternate parts U1 -> ADC3643IRSB
001 (ADC3644): not fitted C57 C65 C80 FID1 FID2 FID3 R10 R15 R23 R58 R62 R63 R66 R68 R69 R74 R76 R82 R86 R94 R107 R109 R120 R121 R123 TP1 TP2 U22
